VERSION 5.8 ;
BUSBITCHARS "" ;
DIVIDERCHAR "/" ;
UNITS DISTANCE MICRONS 2000 ;
# Merged SRAM library: SP (single-port) and DP (dual-port)
# Macros: SP128X33M2, SP128X33M4, SP512X40M2, SP512X40M4, DP128X64M4

MACRO SP128X33M2
  CLASS BLOCK ;
  ORIGIN 0.0 0.0 ;
  SIZE 15.0 BY 30.0 ;
  SYMMETRY X Y ;
  FOREIGN SP128X33M2 0.0 0.0 ;

  PIN CLK
    DIRECTION INPUT ;
    USE SIGNAL ;
    PORT
      LAYER M3 ;
      RECT 3.0 25.0 4.0 26.0 ;
    END
  END CLK

  PIN CS
    DIRECTION INPUT ;
    USE SIGNAL ;
    PORT
      LAYER M3 ;
      RECT 5.0 25.0 6.0 26.0 ;
    END
  END CS

  PIN WE
    DIRECTION INPUT ;
    USE SIGNAL ;
    PORT
      LAYER M3 ;
      RECT 7.0 25.0 8.0 26.0 ;
    END
  END WE

  PIN A[0]
    DIRECTION INPUT ;
    USE SIGNAL ;
    PORT
      LAYER M3 ;
      RECT 9.0 25.0 10.0 26.0 ;
    END
  END A[0]

  PIN A[1]
    DIRECTION INPUT ;
    USE SIGNAL ;
    PORT
      LAYER M3 ;
      RECT 10.0 25.0 11.0 26.0 ;
    END
  END A[1]

  PIN A[2]
    DIRECTION INPUT ;
    USE SIGNAL ;
    PORT
      LAYER M3 ;
      RECT 11.0 25.0 12.0 26.0 ;
    END
  END A[2]

  PIN A[3]
    DIRECTION INPUT ;
    USE SIGNAL ;
    PORT
      LAYER M3 ;
      RECT 12.0 25.0 13.0 26.0 ;
    END
  END A[3]

  PIN A[4]
    DIRECTION INPUT ;
    USE SIGNAL ;
    PORT
      LAYER M3 ;
      RECT 13.0 25.0 14.0 26.0 ;
    END
  END A[4]

  PIN A[5]
    DIRECTION INPUT ;
    USE SIGNAL ;
    PORT
      LAYER M3 ;
      RECT 14.0 25.0 15.0 26.0 ;
    END
  END A[5]

  PIN A[6]
    DIRECTION INPUT ;
    USE SIGNAL ;
    PORT
      LAYER M3 ;
      RECT 15.0 25.0 16.0 26.0 ;
    END
  END A[6]

  PIN D[0]
    DIRECTION INPUT ;
    USE SIGNAL ;
    PORT
      LAYER M3 ;
      RECT 9.0 27.0 10.0 28.0 ;
    END
  END D[0]

  PIN D[1]
    DIRECTION INPUT ;
    USE SIGNAL ;
    PORT
      LAYER M3 ;
      RECT 10.0 27.0 11.0 28.0 ;
    END
  END D[1]

  PIN D[2]
    DIRECTION INPUT ;
    USE SIGNAL ;
    PORT
      LAYER M3 ;
      RECT 11.0 27.0 12.0 28.0 ;
    END
  END D[2]

  PIN D[3]
    DIRECTION INPUT ;
    USE SIGNAL ;
    PORT
      LAYER M3 ;
      RECT 12.0 27.0 13.0 28.0 ;
    END
  END D[3]

  PIN D[4]
    DIRECTION INPUT ;
    USE SIGNAL ;
    PORT
      LAYER M3 ;
      RECT 13.0 27.0 14.0 28.0 ;
    END
  END D[4]

  PIN D[5]
    DIRECTION INPUT ;
    USE SIGNAL ;
    PORT
      LAYER M3 ;
      RECT 14.0 27.0 15.0 28.0 ;
    END
  END D[5]

  PIN D[6]
    DIRECTION INPUT ;
    USE SIGNAL ;
    PORT
      LAYER M3 ;
      RECT 9.0 28.0 10.0 29.0 ;
    END
  END D[6]

  PIN D[7]
    DIRECTION INPUT ;
    USE SIGNAL ;
    PORT
      LAYER M3 ;
      RECT 10.0 28.0 11.0 29.0 ;
    END
  END D[7]

  PIN D[8]
    DIRECTION INPUT ;
    USE SIGNAL ;
    PORT
      LAYER M3 ;
      RECT 11.0 28.0 12.0 29.0 ;
    END
  END D[8]

  PIN D[9]
    DIRECTION INPUT ;
    USE SIGNAL ;
    PORT
      LAYER M3 ;
      RECT 12.0 28.0 13.0 29.0 ;
    END
  END D[9]

  PIN D[10]
    DIRECTION INPUT ;
    USE SIGNAL ;
    PORT
      LAYER M3 ;
      RECT 13.0 28.0 14.0 29.0 ;
    END
  END D[10]

  PIN D[11]
    DIRECTION INPUT ;
    USE SIGNAL ;
    PORT
      LAYER M3 ;
      RECT 14.0 28.0 15.0 29.0 ;
    END
  END D[11]

  PIN D[12]
    DIRECTION INPUT ;
    USE SIGNAL ;
    PORT
      LAYER M3 ;
      RECT 9.0 29.0 10.0 30.0 ;
    END
  END D[12]

  PIN D[13]
    DIRECTION INPUT ;
    USE SIGNAL ;
    PORT
      LAYER M3 ;
      RECT 10.0 29.0 11.0 30.0 ;
    END
  END D[13]

  PIN D[14]
    DIRECTION INPUT ;
    USE SIGNAL ;
    PORT
      LAYER M3 ;
      RECT 11.0 29.0 12.0 30.0 ;
    END
  END D[14]

  PIN D[15]
    DIRECTION INPUT ;
    USE SIGNAL ;
    PORT
      LAYER M3 ;
      RECT 12.0 29.0 13.0 30.0 ;
    END
  END D[15]

  PIN D[16]
    DIRECTION INPUT ;
    USE SIGNAL ;
    PORT
      LAYER M3 ;
      RECT 13.0 29.0 14.0 30.0 ;
    END
  END D[16]

  PIN D[17]
    DIRECTION INPUT ;
    USE SIGNAL ;
    PORT
      LAYER M3 ;
      RECT 14.0 29.0 15.0 30.0 ;
    END
  END D[17]

  PIN D[18]
    DIRECTION INPUT ;
    USE SIGNAL ;
    PORT
      LAYER M3 ;
      RECT 9.0 30.0 10.0 31.0 ;
    END
  END D[18]

  PIN D[19]
    DIRECTION INPUT ;
    USE SIGNAL ;
    PORT
      LAYER M3 ;
      RECT 10.0 30.0 11.0 31.0 ;
    END
  END D[19]

  PIN D[20]
    DIRECTION INPUT ;
    USE SIGNAL ;
    PORT
      LAYER M3 ;
      RECT 11.0 30.0 12.0 31.0 ;
    END
  END D[20]

  PIN D[21]
    DIRECTION INPUT ;
    USE SIGNAL ;
    PORT
      LAYER M3 ;
      RECT 12.0 30.0 13.0 31.0 ;
    END
  END D[21]

  PIN D[22]
    DIRECTION INPUT ;
    USE SIGNAL ;
    PORT
      LAYER M3 ;
      RECT 13.0 30.0 14.0 31.0 ;
    END
  END D[22]

  PIN D[23]
    DIRECTION INPUT ;
    USE SIGNAL ;
    PORT
      LAYER M3 ;
      RECT 14.0 30.0 15.0 31.0 ;
    END
  END D[23]

  PIN D[24]
    DIRECTION INPUT ;
    USE SIGNAL ;
    PORT
      LAYER M3 ;
      RECT 9.0 31.0 10.0 32.0 ;
    END
  END D[24]

  PIN D[25]
    DIRECTION INPUT ;
    USE SIGNAL ;
    PORT
      LAYER M3 ;
      RECT 10.0 31.0 11.0 32.0 ;
    END
  END D[25]

  PIN D[26]
    DIRECTION INPUT ;
    USE SIGNAL ;
    PORT
      LAYER M3 ;
      RECT 11.0 31.0 12.0 32.0 ;
    END
  END D[26]

  PIN D[27]
    DIRECTION INPUT ;
    USE SIGNAL ;
    PORT
      LAYER M3 ;
      RECT 12.0 31.0 13.0 32.0 ;
    END
  END D[27]

  PIN D[28]
    DIRECTION INPUT ;
    USE SIGNAL ;
    PORT
      LAYER M3 ;
      RECT 13.0 31.0 14.0 32.0 ;
    END
  END D[28]

  PIN D[29]
    DIRECTION INPUT ;
    USE SIGNAL ;
    PORT
      LAYER M3 ;
      RECT 14.0 31.0 15.0 32.0 ;
    END
  END D[29]

  PIN D[30]
    DIRECTION INPUT ;
    USE SIGNAL ;
    PORT
      LAYER M3 ;
      RECT 9.0 32.0 10.0 33.0 ;
    END
  END D[30]

  PIN D[31]
    DIRECTION INPUT ;
    USE SIGNAL ;
    PORT
      LAYER M3 ;
      RECT 10.0 32.0 11.0 33.0 ;
    END
  END D[31]

  PIN D[32]
    DIRECTION INPUT ;
    USE SIGNAL ;
    PORT
      LAYER M3 ;
      RECT 11.0 32.0 12.0 33.0 ;
    END
  END D[32]

  PIN Q[0]
    DIRECTION OUTPUT ;
    USE SIGNAL ;
    PORT
      LAYER M3 ;
      RECT 9.0 2.0 10.0 3.0 ;
    END
  END Q[0]

  PIN Q[1]
    DIRECTION OUTPUT ;
    USE SIGNAL ;
    PORT
      LAYER M3 ;
      RECT 10.0 2.0 11.0 3.0 ;
    END
  END Q[1]

  PIN Q[2]
    DIRECTION OUTPUT ;
    USE SIGNAL ;
    PORT
      LAYER M3 ;
      RECT 11.0 2.0 12.0 3.0 ;
    END
  END Q[2]

  PIN Q[3]
    DIRECTION OUTPUT ;
    USE SIGNAL ;
    PORT
      LAYER M3 ;
      RECT 12.0 2.0 13.0 3.0 ;
    END
  END Q[3]

  PIN Q[4]
    DIRECTION OUTPUT ;
    USE SIGNAL ;
    PORT
      LAYER M3 ;
      RECT 13.0 2.0 14.0 3.0 ;
    END
  END Q[4]

  PIN Q[5]
    DIRECTION OUTPUT ;
    USE SIGNAL ;
    PORT
      LAYER M3 ;
      RECT 14.0 2.0 15.0 3.0 ;
    END
  END Q[5]

  PIN Q[6]
    DIRECTION OUTPUT ;
    USE SIGNAL ;
    PORT
      LAYER M3 ;
      RECT 9.0 3.0 10.0 4.0 ;
    END
  END Q[6]

  PIN Q[7]
    DIRECTION OUTPUT ;
    USE SIGNAL ;
    PORT
      LAYER M3 ;
      RECT 10.0 3.0 11.0 4.0 ;
    END
  END Q[7]

  PIN Q[8]
    DIRECTION OUTPUT ;
    USE SIGNAL ;
    PORT
      LAYER M3 ;
      RECT 11.0 3.0 12.0 4.0 ;
    END
  END Q[8]

  PIN Q[9]
    DIRECTION OUTPUT ;
    USE SIGNAL ;
    PORT
      LAYER M3 ;
      RECT 12.0 3.0 13.0 4.0 ;
    END
  END Q[9]

  PIN Q[10]
    DIRECTION OUTPUT ;
    USE SIGNAL ;
    PORT
      LAYER M3 ;
      RECT 13.0 3.0 14.0 4.0 ;
    END
  END Q[10]

  PIN Q[11]
    DIRECTION OUTPUT ;
    USE SIGNAL ;
    PORT
      LAYER M3 ;
      RECT 14.0 3.0 15.0 4.0 ;
    END
  END Q[11]

  PIN Q[12]
    DIRECTION OUTPUT ;
    USE SIGNAL ;
    PORT
      LAYER M3 ;
      RECT 9.0 4.0 10.0 5.0 ;
    END
  END Q[12]

  PIN Q[13]
    DIRECTION OUTPUT ;
    USE SIGNAL ;
    PORT
      LAYER M3 ;
      RECT 10.0 4.0 11.0 5.0 ;
    END
  END Q[13]

  PIN Q[14]
    DIRECTION OUTPUT ;
    USE SIGNAL ;
    PORT
      LAYER M3 ;
      RECT 11.0 4.0 12.0 5.0 ;
    END
  END Q[14]

  PIN Q[15]
    DIRECTION OUTPUT ;
    USE SIGNAL ;
    PORT
      LAYER M3 ;
      RECT 12.0 4.0 13.0 5.0 ;
    END
  END Q[15]

  PIN Q[16]
    DIRECTION OUTPUT ;
    USE SIGNAL ;
    PORT
      LAYER M3 ;
      RECT 13.0 4.0 14.0 5.0 ;
    END
  END Q[16]

  PIN Q[17]
    DIRECTION OUTPUT ;
    USE SIGNAL ;
    PORT
      LAYER M3 ;
      RECT 14.0 4.0 15.0 5.0 ;
    END
  END Q[17]

  PIN Q[18]
    DIRECTION OUTPUT ;
    USE SIGNAL ;
    PORT
      LAYER M3 ;
      RECT 9.0 5.0 10.0 6.0 ;
    END
  END Q[18]

  PIN Q[19]
    DIRECTION OUTPUT ;
    USE SIGNAL ;
    PORT
      LAYER M3 ;
      RECT 10.0 5.0 11.0 6.0 ;
    END
  END Q[19]

  PIN Q[20]
    DIRECTION OUTPUT ;
    USE SIGNAL ;
    PORT
      LAYER M3 ;
      RECT 11.0 5.0 12.0 6.0 ;
    END
  END Q[20]

  PIN Q[21]
    DIRECTION OUTPUT ;
    USE SIGNAL ;
    PORT
      LAYER M3 ;
      RECT 12.0 5.0 13.0 6.0 ;
    END
  END Q[21]

  PIN Q[22]
    DIRECTION OUTPUT ;
    USE SIGNAL ;
    PORT
      LAYER M3 ;
      RECT 13.0 5.0 14.0 6.0 ;
    END
  END Q[22]

  PIN Q[23]
    DIRECTION OUTPUT ;
    USE SIGNAL ;
    PORT
      LAYER M3 ;
      RECT 14.0 5.0 15.0 6.0 ;
    END
  END Q[23]

  PIN Q[24]
    DIRECTION OUTPUT ;
    USE SIGNAL ;
    PORT
      LAYER M3 ;
      RECT 9.0 6.0 10.0 7.0 ;
    END
  END Q[24]

  PIN Q[25]
    DIRECTION OUTPUT ;
    USE SIGNAL ;
    PORT
      LAYER M3 ;
      RECT 10.0 6.0 11.0 7.0 ;
    END
  END Q[25]

  PIN Q[26]
    DIRECTION OUTPUT ;
    USE SIGNAL ;
    PORT
      LAYER M3 ;
      RECT 11.0 6.0 12.0 7.0 ;
    END
  END Q[26]

  PIN Q[27]
    DIRECTION OUTPUT ;
    USE SIGNAL ;
    PORT
      LAYER M3 ;
      RECT 12.0 6.0 13.0 7.0 ;
    END
  END Q[27]

  PIN Q[28]
    DIRECTION OUTPUT ;
    USE SIGNAL ;
    PORT
      LAYER M3 ;
      RECT 13.0 6.0 14.0 7.0 ;
    END
  END Q[28]

  PIN Q[29]
    DIRECTION OUTPUT ;
    USE SIGNAL ;
    PORT
      LAYER M3 ;
      RECT 14.0 6.0 15.0 7.0 ;
    END
  END Q[29]

  PIN Q[30]
    DIRECTION OUTPUT ;
    USE SIGNAL ;
    PORT
      LAYER M3 ;
      RECT 9.0 7.0 10.0 8.0 ;
    END
  END Q[30]

  PIN Q[31]
    DIRECTION OUTPUT ;
    USE SIGNAL ;
    PORT
      LAYER M3 ;
      RECT 10.0 7.0 11.0 8.0 ;
    END
  END Q[31]

  PIN Q[32]
    DIRECTION OUTPUT ;
    USE SIGNAL ;
    PORT
      LAYER M3 ;
      RECT 11.0 7.0 12.0 8.0 ;
    END
  END Q[32]

END SP128X33M2

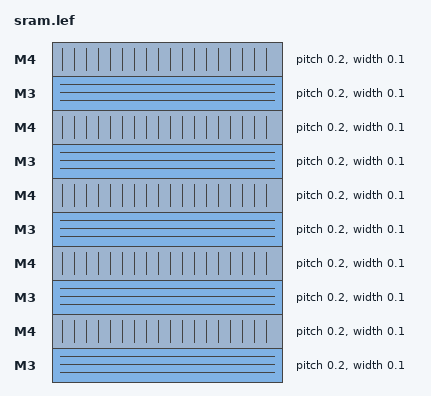
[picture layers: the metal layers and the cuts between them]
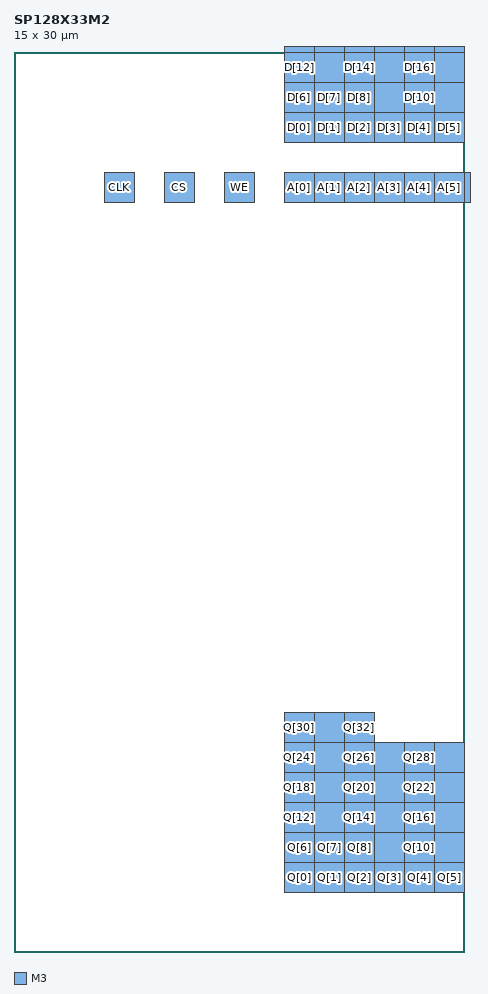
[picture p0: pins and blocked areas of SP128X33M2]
LAYER M3
  TYPE ROUTING ;
  DIRECTION HORIZONTAL ;
  PITCH 0.2 ;
  WIDTH 0.1 ;
END M3

LAYER M4
  TYPE ROUTING ;
  DIRECTION VERTICAL ;
  PITCH 0.2 ;
  WIDTH 0.1 ;
END M4

SITE BLOCK
  CLASS BLOCK ;
  SIZE 1.0 BY 1.0 ;
  SYMMETRY X Y ;
END BLOCK


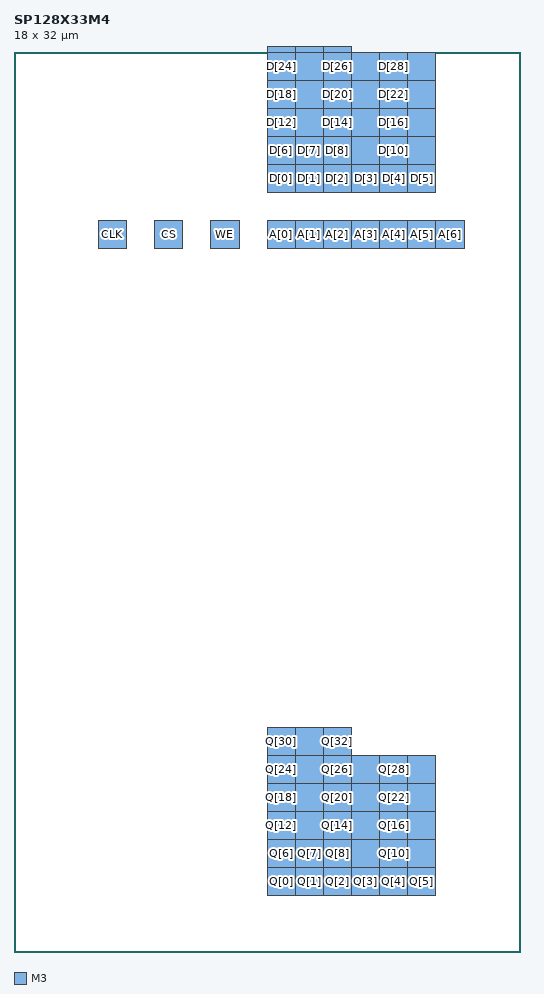
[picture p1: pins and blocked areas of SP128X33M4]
MACRO SP128X33M4
  CLASS BLOCK ;
  ORIGIN 0.0 0.0 ;
  SIZE 18.0 BY 32.0 ;
  SYMMETRY X Y ;
  FOREIGN SP128X33M4 0.0 0.0 ;

  PIN CLK
    DIRECTION INPUT ;
    USE SIGNAL ;
    PORT
      LAYER M3 ;
      RECT 3.0 25.0 4.0 26.0 ;
    END
  END CLK

  PIN CS
    DIRECTION INPUT ;
    USE SIGNAL ;
    PORT
      LAYER M3 ;
      RECT 5.0 25.0 6.0 26.0 ;
    END
  END CS

  PIN WE
    DIRECTION INPUT ;
    USE SIGNAL ;
    PORT
      LAYER M3 ;
      RECT 7.0 25.0 8.0 26.0 ;
    END
  END WE

  PIN A[0]
    DIRECTION INPUT ;
    USE SIGNAL ;
    PORT
      LAYER M3 ;
      RECT 9.0 25.0 10.0 26.0 ;
    END
  END A[0]

  PIN A[1]
    DIRECTION INPUT ;
    USE SIGNAL ;
    PORT
      LAYER M3 ;
      RECT 10.0 25.0 11.0 26.0 ;
    END
  END A[1]

  PIN A[2]
    DIRECTION INPUT ;
    USE SIGNAL ;
    PORT
      LAYER M3 ;
      RECT 11.0 25.0 12.0 26.0 ;
    END
  END A[2]

  PIN A[3]
    DIRECTION INPUT ;
    USE SIGNAL ;
    PORT
      LAYER M3 ;
      RECT 12.0 25.0 13.0 26.0 ;
    END
  END A[3]

  PIN A[4]
    DIRECTION INPUT ;
    USE SIGNAL ;
    PORT
      LAYER M3 ;
      RECT 13.0 25.0 14.0 26.0 ;
    END
  END A[4]

  PIN A[5]
    DIRECTION INPUT ;
    USE SIGNAL ;
    PORT
      LAYER M3 ;
      RECT 14.0 25.0 15.0 26.0 ;
    END
  END A[5]

  PIN A[6]
    DIRECTION INPUT ;
    USE SIGNAL ;
    PORT
      LAYER M3 ;
      RECT 15.0 25.0 16.0 26.0 ;
    END
  END A[6]

  PIN D[0]
    DIRECTION INPUT ;
    USE SIGNAL ;
    PORT
      LAYER M3 ;
      RECT 9.0 27.0 10.0 28.0 ;
    END
  END D[0]

  PIN D[1]
    DIRECTION INPUT ;
    USE SIGNAL ;
    PORT
      LAYER M3 ;
      RECT 10.0 27.0 11.0 28.0 ;
    END
  END D[1]

  PIN D[2]
    DIRECTION INPUT ;
    USE SIGNAL ;
    PORT
      LAYER M3 ;
      RECT 11.0 27.0 12.0 28.0 ;
    END
  END D[2]

  PIN D[3]
    DIRECTION INPUT ;
    USE SIGNAL ;
    PORT
      LAYER M3 ;
      RECT 12.0 27.0 13.0 28.0 ;
    END
  END D[3]

  PIN D[4]
    DIRECTION INPUT ;
    USE SIGNAL ;
    PORT
      LAYER M3 ;
      RECT 13.0 27.0 14.0 28.0 ;
    END
  END D[4]

  PIN D[5]
    DIRECTION INPUT ;
    USE SIGNAL ;
    PORT
      LAYER M3 ;
      RECT 14.0 27.0 15.0 28.0 ;
    END
  END D[5]

  PIN D[6]
    DIRECTION INPUT ;
    USE SIGNAL ;
    PORT
      LAYER M3 ;
      RECT 9.0 28.0 10.0 29.0 ;
    END
  END D[6]

  PIN D[7]
    DIRECTION INPUT ;
    USE SIGNAL ;
    PORT
      LAYER M3 ;
      RECT 10.0 28.0 11.0 29.0 ;
    END
  END D[7]

  PIN D[8]
    DIRECTION INPUT ;
    USE SIGNAL ;
    PORT
      LAYER M3 ;
      RECT 11.0 28.0 12.0 29.0 ;
    END
  END D[8]

  PIN D[9]
    DIRECTION INPUT ;
    USE SIGNAL ;
    PORT
      LAYER M3 ;
      RECT 12.0 28.0 13.0 29.0 ;
    END
  END D[9]

  PIN D[10]
    DIRECTION INPUT ;
    USE SIGNAL ;
    PORT
      LAYER M3 ;
      RECT 13.0 28.0 14.0 29.0 ;
    END
  END D[10]

  PIN D[11]
    DIRECTION INPUT ;
    USE SIGNAL ;
    PORT
      LAYER M3 ;
      RECT 14.0 28.0 15.0 29.0 ;
    END
  END D[11]

  PIN D[12]
    DIRECTION INPUT ;
    USE SIGNAL ;
    PORT
      LAYER M3 ;
      RECT 9.0 29.0 10.0 30.0 ;
    END
  END D[12]

  PIN D[13]
    DIRECTION INPUT ;
    USE SIGNAL ;
    PORT
      LAYER M3 ;
      RECT 10.0 29.0 11.0 30.0 ;
    END
  END D[13]

  PIN D[14]
    DIRECTION INPUT ;
    USE SIGNAL ;
    PORT
      LAYER M3 ;
      RECT 11.0 29.0 12.0 30.0 ;
    END
  END D[14]

  PIN D[15]
    DIRECTION INPUT ;
    USE SIGNAL ;
    PORT
      LAYER M3 ;
      RECT 12.0 29.0 13.0 30.0 ;
    END
  END D[15]

  PIN D[16]
    DIRECTION INPUT ;
    USE SIGNAL ;
    PORT
      LAYER M3 ;
      RECT 13.0 29.0 14.0 30.0 ;
    END
  END D[16]

  PIN D[17]
    DIRECTION INPUT ;
    USE SIGNAL ;
    PORT
      LAYER M3 ;
      RECT 14.0 29.0 15.0 30.0 ;
    END
  END D[17]

  PIN D[18]
    DIRECTION INPUT ;
    USE SIGNAL ;
    PORT
      LAYER M3 ;
      RECT 9.0 30.0 10.0 31.0 ;
    END
  END D[18]

  PIN D[19]
    DIRECTION INPUT ;
    USE SIGNAL ;
    PORT
      LAYER M3 ;
      RECT 10.0 30.0 11.0 31.0 ;
    END
  END D[19]

  PIN D[20]
    DIRECTION INPUT ;
    USE SIGNAL ;
    PORT
      LAYER M3 ;
      RECT 11.0 30.0 12.0 31.0 ;
    END
  END D[20]

  PIN D[21]
    DIRECTION INPUT ;
    USE SIGNAL ;
    PORT
      LAYER M3 ;
      RECT 12.0 30.0 13.0 31.0 ;
    END
  END D[21]

  PIN D[22]
    DIRECTION INPUT ;
    USE SIGNAL ;
    PORT
      LAYER M3 ;
      RECT 13.0 30.0 14.0 31.0 ;
    END
  END D[22]

  PIN D[23]
    DIRECTION INPUT ;
    USE SIGNAL ;
    PORT
      LAYER M3 ;
      RECT 14.0 30.0 15.0 31.0 ;
    END
  END D[23]

  PIN D[24]
    DIRECTION INPUT ;
    USE SIGNAL ;
    PORT
      LAYER M3 ;
      RECT 9.0 31.0 10.0 32.0 ;
    END
  END D[24]

  PIN D[25]
    DIRECTION INPUT ;
    USE SIGNAL ;
    PORT
      LAYER M3 ;
      RECT 10.0 31.0 11.0 32.0 ;
    END
  END D[25]

  PIN D[26]
    DIRECTION INPUT ;
    USE SIGNAL ;
    PORT
      LAYER M3 ;
      RECT 11.0 31.0 12.0 32.0 ;
    END
  END D[26]

  PIN D[27]
    DIRECTION INPUT ;
    USE SIGNAL ;
    PORT
      LAYER M3 ;
      RECT 12.0 31.0 13.0 32.0 ;
    END
  END D[27]

  PIN D[28]
    DIRECTION INPUT ;
    USE SIGNAL ;
    PORT
      LAYER M3 ;
      RECT 13.0 31.0 14.0 32.0 ;
    END
  END D[28]

  PIN D[29]
    DIRECTION INPUT ;
    USE SIGNAL ;
    PORT
      LAYER M3 ;
      RECT 14.0 31.0 15.0 32.0 ;
    END
  END D[29]

  PIN D[30]
    DIRECTION INPUT ;
    USE SIGNAL ;
    PORT
      LAYER M3 ;
      RECT 9.0 32.0 10.0 33.0 ;
    END
  END D[30]

  PIN D[31]
    DIRECTION INPUT ;
    USE SIGNAL ;
    PORT
      LAYER M3 ;
      RECT 10.0 32.0 11.0 33.0 ;
    END
  END D[31]

  PIN D[32]
    DIRECTION INPUT ;
    USE SIGNAL ;
    PORT
      LAYER M3 ;
      RECT 11.0 32.0 12.0 33.0 ;
    END
  END D[32]

  PIN Q[0]
    DIRECTION OUTPUT ;
    USE SIGNAL ;
    PORT
      LAYER M3 ;
      RECT 9.0 2.0 10.0 3.0 ;
    END
  END Q[0]

  PIN Q[1]
    DIRECTION OUTPUT ;
    USE SIGNAL ;
    PORT
      LAYER M3 ;
      RECT 10.0 2.0 11.0 3.0 ;
    END
  END Q[1]

  PIN Q[2]
    DIRECTION OUTPUT ;
    USE SIGNAL ;
    PORT
      LAYER M3 ;
      RECT 11.0 2.0 12.0 3.0 ;
    END
  END Q[2]

  PIN Q[3]
    DIRECTION OUTPUT ;
    USE SIGNAL ;
    PORT
      LAYER M3 ;
      RECT 12.0 2.0 13.0 3.0 ;
    END
  END Q[3]

  PIN Q[4]
    DIRECTION OUTPUT ;
    USE SIGNAL ;
    PORT
      LAYER M3 ;
      RECT 13.0 2.0 14.0 3.0 ;
    END
  END Q[4]

  PIN Q[5]
    DIRECTION OUTPUT ;
    USE SIGNAL ;
    PORT
      LAYER M3 ;
      RECT 14.0 2.0 15.0 3.0 ;
    END
  END Q[5]

  PIN Q[6]
    DIRECTION OUTPUT ;
    USE SIGNAL ;
    PORT
      LAYER M3 ;
      RECT 9.0 3.0 10.0 4.0 ;
    END
  END Q[6]

  PIN Q[7]
    DIRECTION OUTPUT ;
    USE SIGNAL ;
    PORT
      LAYER M3 ;
      RECT 10.0 3.0 11.0 4.0 ;
    END
  END Q[7]

  PIN Q[8]
    DIRECTION OUTPUT ;
    USE SIGNAL ;
    PORT
      LAYER M3 ;
      RECT 11.0 3.0 12.0 4.0 ;
    END
  END Q[8]

  PIN Q[9]
    DIRECTION OUTPUT ;
    USE SIGNAL ;
    PORT
      LAYER M3 ;
      RECT 12.0 3.0 13.0 4.0 ;
    END
  END Q[9]

  PIN Q[10]
    DIRECTION OUTPUT ;
    USE SIGNAL ;
    PORT
      LAYER M3 ;
      RECT 13.0 3.0 14.0 4.0 ;
    END
  END Q[10]

  PIN Q[11]
    DIRECTION OUTPUT ;
    USE SIGNAL ;
    PORT
      LAYER M3 ;
      RECT 14.0 3.0 15.0 4.0 ;
    END
  END Q[11]

  PIN Q[12]
    DIRECTION OUTPUT ;
    USE SIGNAL ;
    PORT
      LAYER M3 ;
      RECT 9.0 4.0 10.0 5.0 ;
    END
  END Q[12]

  PIN Q[13]
    DIRECTION OUTPUT ;
    USE SIGNAL ;
    PORT
      LAYER M3 ;
      RECT 10.0 4.0 11.0 5.0 ;
    END
  END Q[13]

  PIN Q[14]
    DIRECTION OUTPUT ;
    USE SIGNAL ;
    PORT
      LAYER M3 ;
      RECT 11.0 4.0 12.0 5.0 ;
    END
  END Q[14]

  PIN Q[15]
    DIRECTION OUTPUT ;
    USE SIGNAL ;
    PORT
      LAYER M3 ;
      RECT 12.0 4.0 13.0 5.0 ;
    END
  END Q[15]

  PIN Q[16]
    DIRECTION OUTPUT ;
    USE SIGNAL ;
    PORT
      LAYER M3 ;
      RECT 13.0 4.0 14.0 5.0 ;
    END
  END Q[16]

  PIN Q[17]
    DIRECTION OUTPUT ;
    USE SIGNAL ;
    PORT
      LAYER M3 ;
      RECT 14.0 4.0 15.0 5.0 ;
    END
  END Q[17]

  PIN Q[18]
    DIRECTION OUTPUT ;
    USE SIGNAL ;
    PORT
      LAYER M3 ;
      RECT 9.0 5.0 10.0 6.0 ;
    END
  END Q[18]

  PIN Q[19]
    DIRECTION OUTPUT ;
    USE SIGNAL ;
    PORT
      LAYER M3 ;
      RECT 10.0 5.0 11.0 6.0 ;
    END
  END Q[19]

  PIN Q[20]
    DIRECTION OUTPUT ;
    USE SIGNAL ;
    PORT
      LAYER M3 ;
      RECT 11.0 5.0 12.0 6.0 ;
    END
  END Q[20]

  PIN Q[21]
    DIRECTION OUTPUT ;
    USE SIGNAL ;
    PORT
      LAYER M3 ;
      RECT 12.0 5.0 13.0 6.0 ;
    END
  END Q[21]

  PIN Q[22]
    DIRECTION OUTPUT ;
    USE SIGNAL ;
    PORT
      LAYER M3 ;
      RECT 13.0 5.0 14.0 6.0 ;
    END
  END Q[22]

  PIN Q[23]
    DIRECTION OUTPUT ;
    USE SIGNAL ;
    PORT
      LAYER M3 ;
      RECT 14.0 5.0 15.0 6.0 ;
    END
  END Q[23]

  PIN Q[24]
    DIRECTION OUTPUT ;
    USE SIGNAL ;
    PORT
      LAYER M3 ;
      RECT 9.0 6.0 10.0 7.0 ;
    END
  END Q[24]

  PIN Q[25]
    DIRECTION OUTPUT ;
    USE SIGNAL ;
    PORT
      LAYER M3 ;
      RECT 10.0 6.0 11.0 7.0 ;
    END
  END Q[25]

  PIN Q[26]
    DIRECTION OUTPUT ;
    USE SIGNAL ;
    PORT
      LAYER M3 ;
      RECT 11.0 6.0 12.0 7.0 ;
    END
  END Q[26]

  PIN Q[27]
    DIRECTION OUTPUT ;
    USE SIGNAL ;
    PORT
      LAYER M3 ;
      RECT 12.0 6.0 13.0 7.0 ;
    END
  END Q[27]

  PIN Q[28]
    DIRECTION OUTPUT ;
    USE SIGNAL ;
    PORT
      LAYER M3 ;
      RECT 13.0 6.0 14.0 7.0 ;
    END
  END Q[28]

  PIN Q[29]
    DIRECTION OUTPUT ;
    USE SIGNAL ;
    PORT
      LAYER M3 ;
      RECT 14.0 6.0 15.0 7.0 ;
    END
  END Q[29]

  PIN Q[30]
    DIRECTION OUTPUT ;
    USE SIGNAL ;
    PORT
      LAYER M3 ;
      RECT 9.0 7.0 10.0 8.0 ;
    END
  END Q[30]

  PIN Q[31]
    DIRECTION OUTPUT ;
    USE SIGNAL ;
    PORT
      LAYER M3 ;
      RECT 10.0 7.0 11.0 8.0 ;
    END
  END Q[31]

  PIN Q[32]
    DIRECTION OUTPUT ;
    USE SIGNAL ;
    PORT
      LAYER M3 ;
      RECT 11.0 7.0 12.0 8.0 ;
    END
  END Q[32]

END SP128X33M4

LAYER M3
  TYPE ROUTING ;
  DIRECTION HORIZONTAL ;
  PITCH 0.2 ;
  WIDTH 0.1 ;
END M3

LAYER M4
  TYPE ROUTING ;
  DIRECTION VERTICAL ;
  PITCH 0.2 ;
  WIDTH 0.1 ;
END M4

SITE BLOCK
  CLASS BLOCK ;
  SIZE 1.0 BY 1.0 ;
  SYMMETRY X Y ;
END BLOCK


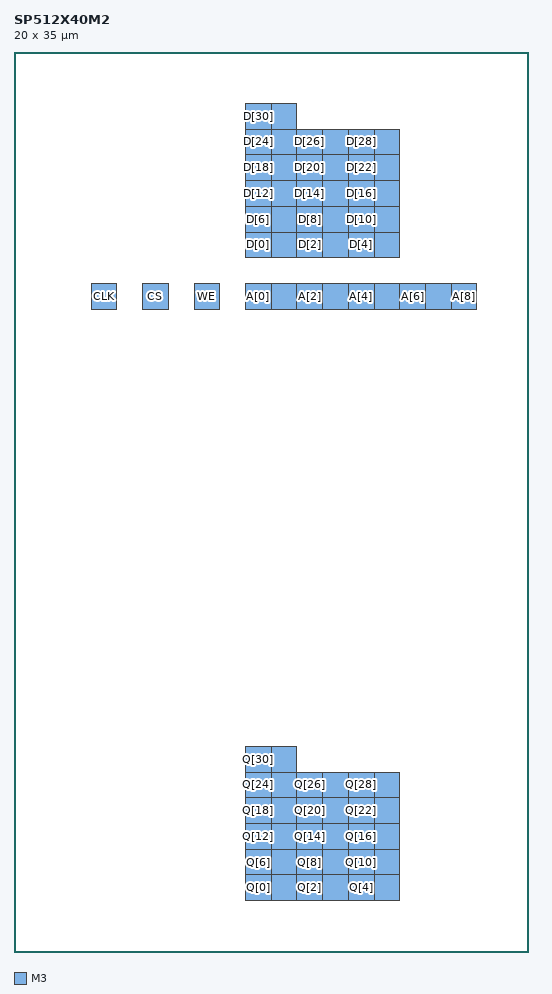
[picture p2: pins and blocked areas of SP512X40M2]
MACRO SP512X40M2
  CLASS BLOCK ;
  ORIGIN 0.0 0.0 ;
  SIZE 20.0 BY 35.0 ;
  SYMMETRY X Y ;
  FOREIGN SP512X40M2 0.0 0.0 ;

  PIN CLK
    DIRECTION INPUT ;
    USE SIGNAL ;
    PORT
      LAYER M3 ;
      RECT 3.0 25.0 4.0 26.0 ;
    END
  END CLK

  PIN CS
    DIRECTION INPUT ;
    USE SIGNAL ;
    PORT
      LAYER M3 ;
      RECT 5.0 25.0 6.0 26.0 ;
    END
  END CS

  PIN WE
    DIRECTION INPUT ;
    USE SIGNAL ;
    PORT
      LAYER M3 ;
      RECT 7.0 25.0 8.0 26.0 ;
    END
  END WE

  PIN A[0]
    DIRECTION INPUT ;
    USE SIGNAL ;
    PORT
      LAYER M3 ;
      RECT 9.0 25.0 10.0 26.0 ;
    END
  END A[0]

  PIN A[1]
    DIRECTION INPUT ;
    USE SIGNAL ;
    PORT
      LAYER M3 ;
      RECT 10.0 25.0 11.0 26.0 ;
    END
  END A[1]

  PIN A[2]
    DIRECTION INPUT ;
    USE SIGNAL ;
    PORT
      LAYER M3 ;
      RECT 11.0 25.0 12.0 26.0 ;
    END
  END A[2]

  PIN A[3]
    DIRECTION INPUT ;
    USE SIGNAL ;
    PORT
      LAYER M3 ;
      RECT 12.0 25.0 13.0 26.0 ;
    END
  END A[3]

  PIN A[4]
    DIRECTION INPUT ;
    USE SIGNAL ;
    PORT
      LAYER M3 ;
      RECT 13.0 25.0 14.0 26.0 ;
    END
  END A[4]

  PIN A[5]
    DIRECTION INPUT ;
    USE SIGNAL ;
    PORT
      LAYER M3 ;
      RECT 14.0 25.0 15.0 26.0 ;
    END
  END A[5]

  PIN A[6]
    DIRECTION INPUT ;
    USE SIGNAL ;
    PORT
      LAYER M3 ;
      RECT 15.0 25.0 16.0 26.0 ;
    END
  END A[6]

  PIN A[7]
    DIRECTION INPUT ;
    USE SIGNAL ;
    PORT
      LAYER M3 ;
      RECT 16.0 25.0 17.0 26.0 ;
    END
  END A[7]

  PIN A[8]
    DIRECTION INPUT ;
    USE SIGNAL ;
    PORT
      LAYER M3 ;
      RECT 17.0 25.0 18.0 26.0 ;
    END
  END A[8]

  PIN D[0]
    DIRECTION INPUT ;
    USE SIGNAL ;
    PORT
      LAYER M3 ;
      RECT 9.0 27.0 10.0 28.0 ;
    END
  END D[0]

  PIN D[1]
    DIRECTION INPUT ;
    USE SIGNAL ;
    PORT
      LAYER M3 ;
      RECT 10.0 27.0 11.0 28.0 ;
    END
  END D[1]

  PIN D[2]
    DIRECTION INPUT ;
    USE SIGNAL ;
    PORT
      LAYER M3 ;
      RECT 11.0 27.0 12.0 28.0 ;
    END
  END D[2]

  PIN D[3]
    DIRECTION INPUT ;
    USE SIGNAL ;
    PORT
      LAYER M3 ;
      RECT 12.0 27.0 13.0 28.0 ;
    END
  END D[3]

  PIN D[4]
    DIRECTION INPUT ;
    USE SIGNAL ;
    PORT
      LAYER M3 ;
      RECT 13.0 27.0 14.0 28.0 ;
    END
  END D[4]

  PIN D[5]
    DIRECTION INPUT ;
    USE SIGNAL ;
    PORT
      LAYER M3 ;
      RECT 14.0 27.0 15.0 28.0 ;
    END
  END D[5]

  PIN D[6]
    DIRECTION INPUT ;
    USE SIGNAL ;
    PORT
      LAYER M3 ;
      RECT 9.0 28.0 10.0 29.0 ;
    END
  END D[6]

  PIN D[7]
    DIRECTION INPUT ;
    USE SIGNAL ;
    PORT
      LAYER M3 ;
      RECT 10.0 28.0 11.0 29.0 ;
    END
  END D[7]

  PIN D[8]
    DIRECTION INPUT ;
    USE SIGNAL ;
    PORT
      LAYER M3 ;
      RECT 11.0 28.0 12.0 29.0 ;
    END
  END D[8]

  PIN D[9]
    DIRECTION INPUT ;
    USE SIGNAL ;
    PORT
      LAYER M3 ;
      RECT 12.0 28.0 13.0 29.0 ;
    END
  END D[9]

  PIN D[10]
    DIRECTION INPUT ;
    USE SIGNAL ;
    PORT
      LAYER M3 ;
      RECT 13.0 28.0 14.0 29.0 ;
    END
  END D[10]

  PIN D[11]
    DIRECTION INPUT ;
    USE SIGNAL ;
    PORT
      LAYER M3 ;
      RECT 14.0 28.0 15.0 29.0 ;
    END
  END D[11]

  PIN D[12]
    DIRECTION INPUT ;
    USE SIGNAL ;
    PORT
      LAYER M3 ;
      RECT 9.0 29.0 10.0 30.0 ;
    END
  END D[12]

  PIN D[13]
    DIRECTION INPUT ;
    USE SIGNAL ;
    PORT
      LAYER M3 ;
      RECT 10.0 29.0 11.0 30.0 ;
    END
  END D[13]

  PIN D[14]
    DIRECTION INPUT ;
    USE SIGNAL ;
    PORT
      LAYER M3 ;
      RECT 11.0 29.0 12.0 30.0 ;
    END
  END D[14]

  PIN D[15]
    DIRECTION INPUT ;
    USE SIGNAL ;
    PORT
      LAYER M3 ;
      RECT 12.0 29.0 13.0 30.0 ;
    END
  END D[15]

  PIN D[16]
    DIRECTION INPUT ;
    USE SIGNAL ;
    PORT
      LAYER M3 ;
      RECT 13.0 29.0 14.0 30.0 ;
    END
  END D[16]

  PIN D[17]
    DIRECTION INPUT ;
    USE SIGNAL ;
    PORT
      LAYER M3 ;
      RECT 14.0 29.0 15.0 30.0 ;
    END
  END D[17]

  PIN D[18]
    DIRECTION INPUT ;
    USE SIGNAL ;
    PORT
      LAYER M3 ;
      RECT 9.0 30.0 10.0 31.0 ;
    END
  END D[18]

  PIN D[19]
    DIRECTION INPUT ;
    USE SIGNAL ;
    PORT
      LAYER M3 ;
      RECT 10.0 30.0 11.0 31.0 ;
    END
  END D[19]

  PIN D[20]
    DIRECTION INPUT ;
    USE SIGNAL ;
    PORT
      LAYER M3 ;
      RECT 11.0 30.0 12.0 31.0 ;
    END
  END D[20]

  PIN D[21]
    DIRECTION INPUT ;
    USE SIGNAL ;
    PORT
      LAYER M3 ;
      RECT 12.0 30.0 13.0 31.0 ;
    END
  END D[21]

  PIN D[22]
    DIRECTION INPUT ;
    USE SIGNAL ;
    PORT
      LAYER M3 ;
      RECT 13.0 30.0 14.0 31.0 ;
    END
  END D[22]

  PIN D[23]
    DIRECTION INPUT ;
    USE SIGNAL ;
    PORT
      LAYER M3 ;
      RECT 14.0 30.0 15.0 31.0 ;
    END
  END D[23]

  PIN D[24]
    DIRECTION INPUT ;
    USE SIGNAL ;
    PORT
      LAYER M3 ;
      RECT 9.0 31.0 10.0 32.0 ;
    END
  END D[24]

  PIN D[25]
    DIRECTION INPUT ;
    USE SIGNAL ;
    PORT
      LAYER M3 ;
      RECT 10.0 31.0 11.0 32.0 ;
    END
  END D[25]

  PIN D[26]
    DIRECTION INPUT ;
    USE SIGNAL ;
    PORT
      LAYER M3 ;
      RECT 11.0 31.0 12.0 32.0 ;
    END
  END D[26]

  PIN D[27]
    DIRECTION INPUT ;
    USE SIGNAL ;
    PORT
      LAYER M3 ;
      RECT 12.0 31.0 13.0 32.0 ;
    END
  END D[27]

  PIN D[28]
    DIRECTION INPUT ;
    USE SIGNAL ;
    PORT
      LAYER M3 ;
      RECT 13.0 31.0 14.0 32.0 ;
    END
  END D[28]

  PIN D[29]
    DIRECTION INPUT ;
    USE SIGNAL ;
    PORT
      LAYER M3 ;
      RECT 14.0 31.0 15.0 32.0 ;
    END
  END D[29]

  PIN D[30]
    DIRECTION INPUT ;
    USE SIGNAL ;
    PORT
      LAYER M3 ;
      RECT 9.0 32.0 10.0 33.0 ;
    END
  END D[30]

  PIN D[31]
    DIRECTION INPUT ;
    USE SIGNAL ;
    PORT
      LAYER M3 ;
      RECT 10.0 32.0 11.0 33.0 ;
    END
  END D[31]

  PIN Q[0]
    DIRECTION OUTPUT ;
    USE SIGNAL ;
    PORT
      LAYER M3 ;
      RECT 9.0 2.0 10.0 3.0 ;
    END
  END Q[0]

  PIN Q[1]
    DIRECTION OUTPUT ;
    USE SIGNAL ;
    PORT
      LAYER M3 ;
      RECT 10.0 2.0 11.0 3.0 ;
    END
  END Q[1]

  PIN Q[2]
    DIRECTION OUTPUT ;
    USE SIGNAL ;
    PORT
      LAYER M3 ;
      RECT 11.0 2.0 12.0 3.0 ;
    END
  END Q[2]

  PIN Q[3]
    DIRECTION OUTPUT ;
    USE SIGNAL ;
    PORT
      LAYER M3 ;
      RECT 12.0 2.0 13.0 3.0 ;
    END
  END Q[3]

  PIN Q[4]
    DIRECTION OUTPUT ;
    USE SIGNAL ;
    PORT
      LAYER M3 ;
      RECT 13.0 2.0 14.0 3.0 ;
    END
  END Q[4]

  PIN Q[5]
    DIRECTION OUTPUT ;
    USE SIGNAL ;
    PORT
      LAYER M3 ;
      RECT 14.0 2.0 15.0 3.0 ;
    END
  END Q[5]

  PIN Q[6]
    DIRECTION OUTPUT ;
    USE SIGNAL ;
    PORT
      LAYER M3 ;
      RECT 9.0 3.0 10.0 4.0 ;
    END
  END Q[6]

  PIN Q[7]
    DIRECTION OUTPUT ;
    USE SIGNAL ;
    PORT
      LAYER M3 ;
      RECT 10.0 3.0 11.0 4.0 ;
    END
  END Q[7]

  PIN Q[8]
    DIRECTION OUTPUT ;
    USE SIGNAL ;
    PORT
      LAYER M3 ;
      RECT 11.0 3.0 12.0 4.0 ;
    END
  END Q[8]

  PIN Q[9]
    DIRECTION OUTPUT ;
    USE SIGNAL ;
    PORT
      LAYER M3 ;
      RECT 12.0 3.0 13.0 4.0 ;
    END
  END Q[9]

  PIN Q[10]
    DIRECTION OUTPUT ;
    USE SIGNAL ;
    PORT
      LAYER M3 ;
      RECT 13.0 3.0 14.0 4.0 ;
    END
  END Q[10]

  PIN Q[11]
    DIRECTION OUTPUT ;
    USE SIGNAL ;
    PORT
      LAYER M3 ;
      RECT 14.0 3.0 15.0 4.0 ;
    END
  END Q[11]

  PIN Q[12]
    DIRECTION OUTPUT ;
    USE SIGNAL ;
    PORT
      LAYER M3 ;
      RECT 9.0 4.0 10.0 5.0 ;
    END
  END Q[12]

  PIN Q[13]
    DIRECTION OUTPUT ;
    USE SIGNAL ;
    PORT
      LAYER M3 ;
      RECT 10.0 4.0 11.0 5.0 ;
    END
  END Q[13]

  PIN Q[14]
    DIRECTION OUTPUT ;
    USE SIGNAL ;
    PORT
      LAYER M3 ;
      RECT 11.0 4.0 12.0 5.0 ;
    END
  END Q[14]

  PIN Q[15]
    DIRECTION OUTPUT ;
    USE SIGNAL ;
    PORT
      LAYER M3 ;
      RECT 12.0 4.0 13.0 5.0 ;
    END
  END Q[15]

  PIN Q[16]
    DIRECTION OUTPUT ;
    USE SIGNAL ;
    PORT
      LAYER M3 ;
      RECT 13.0 4.0 14.0 5.0 ;
    END
  END Q[16]

  PIN Q[17]
    DIRECTION OUTPUT ;
    USE SIGNAL ;
    PORT
      LAYER M3 ;
      RECT 14.0 4.0 15.0 5.0 ;
    END
  END Q[17]

  PIN Q[18]
    DIRECTION OUTPUT ;
    USE SIGNAL ;
    PORT
      LAYER M3 ;
      RECT 9.0 5.0 10.0 6.0 ;
    END
  END Q[18]

  PIN Q[19]
    DIRECTION OUTPUT ;
    USE SIGNAL ;
    PORT
      LAYER M3 ;
      RECT 10.0 5.0 11.0 6.0 ;
    END
  END Q[19]

  PIN Q[20]
    DIRECTION OUTPUT ;
    USE SIGNAL ;
    PORT
      LAYER M3 ;
      RECT 11.0 5.0 12.0 6.0 ;
    END
  END Q[20]

  PIN Q[21]
    DIRECTION OUTPUT ;
    USE SIGNAL ;
    PORT
      LAYER M3 ;
      RECT 12.0 5.0 13.0 6.0 ;
    END
  END Q[21]

  PIN Q[22]
    DIRECTION OUTPUT ;
    USE SIGNAL ;
    PORT
      LAYER M3 ;
      RECT 13.0 5.0 14.0 6.0 ;
    END
  END Q[22]

  PIN Q[23]
    DIRECTION OUTPUT ;
    USE SIGNAL ;
    PORT
      LAYER M3 ;
      RECT 14.0 5.0 15.0 6.0 ;
    END
  END Q[23]

  PIN Q[24]
    DIRECTION OUTPUT ;
    USE SIGNAL ;
    PORT
      LAYER M3 ;
      RECT 9.0 6.0 10.0 7.0 ;
    END
  END Q[24]

  PIN Q[25]
    DIRECTION OUTPUT ;
    USE SIGNAL ;
    PORT
      LAYER M3 ;
      RECT 10.0 6.0 11.0 7.0 ;
    END
  END Q[25]

  PIN Q[26]
    DIRECTION OUTPUT ;
    USE SIGNAL ;
    PORT
      LAYER M3 ;
      RECT 11.0 6.0 12.0 7.0 ;
    END
  END Q[26]

  PIN Q[27]
    DIRECTION OUTPUT ;
    USE SIGNAL ;
    PORT
      LAYER M3 ;
      RECT 12.0 6.0 13.0 7.0 ;
    END
  END Q[27]

  PIN Q[28]
    DIRECTION OUTPUT ;
    USE SIGNAL ;
    PORT
      LAYER M3 ;
      RECT 13.0 6.0 14.0 7.0 ;
    END
  END Q[28]

  PIN Q[29]
    DIRECTION OUTPUT ;
    USE SIGNAL ;
    PORT
      LAYER M3 ;
      RECT 14.0 6.0 15.0 7.0 ;
    END
  END Q[29]

  PIN Q[30]
    DIRECTION OUTPUT ;
    USE SIGNAL ;
    PORT
      LAYER M3 ;
      RECT 9.0 7.0 10.0 8.0 ;
    END
  END Q[30]

  PIN Q[31]
    DIRECTION OUTPUT ;
    USE SIGNAL ;
    PORT
      LAYER M3 ;
      RECT 10.0 7.0 11.0 8.0 ;
    END
  END Q[31]

END SP512X40M2

LAYER M3
  TYPE ROUTING ;
  DIRECTION HORIZONTAL ;
  PITCH 0.2 ;
  WIDTH 0.1 ;
END M3

LAYER M4
  TYPE ROUTING ;
  DIRECTION VERTICAL ;
  PITCH 0.2 ;
  WIDTH 0.1 ;
END M4

SITE BLOCK
  CLASS BLOCK ;
  SIZE 1.0 BY 1.0 ;
  SYMMETRY X Y ;
END BLOCK


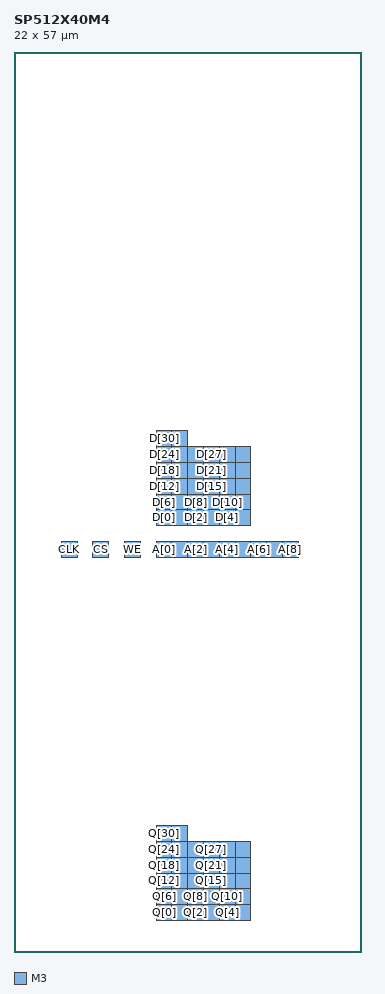
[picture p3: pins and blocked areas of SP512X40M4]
MACRO SP512X40M4
  CLASS BLOCK ;
  ORIGIN 0.0 0.0 ;
  SIZE 22.0 BY 57.0 ;
  SYMMETRY X Y ;
  FOREIGN SP512X40M4 0.0 0.0 ;

  PIN CLK
    DIRECTION INPUT ;
    USE SIGNAL ;
    PORT
      LAYER M3 ;
      RECT 3.0 25.0 4.0 26.0 ;
    END
  END CLK

  PIN CS
    DIRECTION INPUT ;
    USE SIGNAL ;
    PORT
      LAYER M3 ;
      RECT 5.0 25.0 6.0 26.0 ;
    END
  END CS

  PIN WE
    DIRECTION INPUT ;
    USE SIGNAL ;
    PORT
      LAYER M3 ;
      RECT 7.0 25.0 8.0 26.0 ;
    END
  END WE

  PIN A[0]
    DIRECTION INPUT ;
    USE SIGNAL ;
    PORT
      LAYER M3 ;
      RECT 9.0 25.0 10.0 26.0 ;
    END
  END A[0]

  PIN A[1]
    DIRECTION INPUT ;
    USE SIGNAL ;
    PORT
      LAYER M3 ;
      RECT 10.0 25.0 11.0 26.0 ;
    END
  END A[1]

  PIN A[2]
    DIRECTION INPUT ;
    USE SIGNAL ;
    PORT
      LAYER M3 ;
      RECT 11.0 25.0 12.0 26.0 ;
    END
  END A[2]

  PIN A[3]
    DIRECTION INPUT ;
    USE SIGNAL ;
    PORT
      LAYER M3 ;
      RECT 12.0 25.0 13.0 26.0 ;
    END
  END A[3]

  PIN A[4]
    DIRECTION INPUT ;
    USE SIGNAL ;
    PORT
      LAYER M3 ;
      RECT 13.0 25.0 14.0 26.0 ;
    END
  END A[4]

  PIN A[5]
    DIRECTION INPUT ;
    USE SIGNAL ;
    PORT
      LAYER M3 ;
      RECT 14.0 25.0 15.0 26.0 ;
    END
  END A[5]

  PIN A[6]
    DIRECTION INPUT ;
    USE SIGNAL ;
    PORT
      LAYER M3 ;
      RECT 15.0 25.0 16.0 26.0 ;
    END
  END A[6]

  PIN A[7]
    DIRECTION INPUT ;
    USE SIGNAL ;
    PORT
      LAYER M3 ;
      RECT 16.0 25.0 17.0 26.0 ;
    END
  END A[7]

  PIN A[8]
    DIRECTION INPUT ;
    USE SIGNAL ;
    PORT
      LAYER M3 ;
      RECT 17.0 25.0 18.0 26.0 ;
    END
  END A[8]

  PIN D[0]
    DIRECTION INPUT ;
    USE SIGNAL ;
    PORT
      LAYER M3 ;
      RECT 9.0 27.0 10.0 28.0 ;
    END
  END D[0]

  PIN D[1]
    DIRECTION INPUT ;
    USE SIGNAL ;
    PORT
      LAYER M3 ;
      RECT 10.0 27.0 11.0 28.0 ;
    END
  END D[1]

  PIN D[2]
    DIRECTION INPUT ;
    USE SIGNAL ;
    PORT
      LAYER M3 ;
      RECT 11.0 27.0 12.0 28.0 ;
    END
  END D[2]

  PIN D[3]
    DIRECTION INPUT ;
    USE SIGNAL ;
    PORT
      LAYER M3 ;
      RECT 12.0 27.0 13.0 28.0 ;
    END
  END D[3]

  PIN D[4]
    DIRECTION INPUT ;
    USE SIGNAL ;
    PORT
      LAYER M3 ;
      RECT 13.0 27.0 14.0 28.0 ;
    END
  END D[4]

  PIN D[5]
    DIRECTION INPUT ;
    USE SIGNAL ;
    PORT
      LAYER M3 ;
      RECT 14.0 27.0 15.0 28.0 ;
    END
  END D[5]

  PIN D[6]
    DIRECTION INPUT ;
    USE SIGNAL ;
    PORT
      LAYER M3 ;
      RECT 9.0 28.0 10.0 29.0 ;
    END
  END D[6]

  PIN D[7]
    DIRECTION INPUT ;
    USE SIGNAL ;
    PORT
      LAYER M3 ;
      RECT 10.0 28.0 11.0 29.0 ;
    END
  END D[7]

  PIN D[8]
    DIRECTION INPUT ;
    USE SIGNAL ;
    PORT
      LAYER M3 ;
      RECT 11.0 28.0 12.0 29.0 ;
    END
  END D[8]

  PIN D[9]
    DIRECTION INPUT ;
    USE SIGNAL ;
    PORT
      LAYER M3 ;
      RECT 12.0 28.0 13.0 29.0 ;
    END
  END D[9]

  PIN D[10]
    DIRECTION INPUT ;
    USE SIGNAL ;
    PORT
      LAYER M3 ;
      RECT 13.0 28.0 14.0 29.0 ;
    END
  END D[10]

  PIN D[11]
    DIRECTION INPUT ;
    USE SIGNAL ;
    PORT
      LAYER M3 ;
      RECT 14.0 28.0 15.0 29.0 ;
    END
  END D[11]

  PIN D[12]
    DIRECTION INPUT ;
    USE SIGNAL ;
    PORT
      LAYER M3 ;
      RECT 9.0 29.0 10.0 30.0 ;
    END
  END D[12]

  PIN D[13]
    DIRECTION INPUT ;
    USE SIGNAL ;
    PORT
      LAYER M3 ;
      RECT 10.0 29.0 11.0 30.0 ;
    END
  END D[13]

  PIN D[14]
    DIRECTION INPUT ;
    USE SIGNAL ;
    PORT
      LAYER M3 ;
      RECT 11.0 29.0 12.0 30.0 ;
    END
  END D[14]

  PIN D[15]
    DIRECTION INPUT ;
    USE SIGNAL ;
    PORT
      LAYER M3 ;
      RECT 12.0 29.0 13.0 30.0 ;
    END
  END D[15]

  PIN D[16]
    DIRECTION INPUT ;
    USE SIGNAL ;
    PORT
      LAYER M3 ;
      RECT 13.0 29.0 14.0 30.0 ;
    END
  END D[16]

  PIN D[17]
    DIRECTION INPUT ;
    USE SIGNAL ;
    PORT
      LAYER M3 ;
      RECT 14.0 29.0 15.0 30.0 ;
    END
  END D[17]

  PIN D[18]
    DIRECTION INPUT ;
    USE SIGNAL ;
    PORT
      LAYER M3 ;
      RECT 9.0 30.0 10.0 31.0 ;
    END
  END D[18]

  PIN D[19]
    DIRECTION INPUT ;
    USE SIGNAL ;
    PORT
      LAYER M3 ;
      RECT 10.0 30.0 11.0 31.0 ;
    END
  END D[19]

  PIN D[20]
    DIRECTION INPUT ;
    USE SIGNAL ;
    PORT
      LAYER M3 ;
      RECT 11.0 30.0 12.0 31.0 ;
    END
  END D[20]

  PIN D[21]
    DIRECTION INPUT ;
    USE SIGNAL ;
    PORT
      LAYER M3 ;
      RECT 12.0 30.0 13.0 31.0 ;
    END
  END D[21]

  PIN D[22]
    DIRECTION INPUT ;
    USE SIGNAL ;
    PORT
      LAYER M3 ;
      RECT 13.0 30.0 14.0 31.0 ;
    END
  END D[22]

  PIN D[23]
    DIRECTION INPUT ;
    USE SIGNAL ;
    PORT
      LAYER M3 ;
      RECT 14.0 30.0 15.0 31.0 ;
    END
  END D[23]

  PIN D[24]
    DIRECTION INPUT ;
    USE SIGNAL ;
    PORT
      LAYER M3 ;
      RECT 9.0 31.0 10.0 32.0 ;
    END
  END D[24]

  PIN D[25]
    DIRECTION INPUT ;
    USE SIGNAL ;
    PORT
      LAYER M3 ;
      RECT 10.0 31.0 11.0 32.0 ;
    END
  END D[25]

  PIN D[26]
    DIRECTION INPUT ;
    USE SIGNAL ;
    PORT
      LAYER M3 ;
      RECT 11.0 31.0 12.0 32.0 ;
    END
  END D[26]

  PIN D[27]
    DIRECTION INPUT ;
    USE SIGNAL ;
    PORT
      LAYER M3 ;
      RECT 12.0 31.0 13.0 32.0 ;
    END
  END D[27]

  PIN D[28]
    DIRECTION INPUT ;
    USE SIGNAL ;
    PORT
      LAYER M3 ;
      RECT 13.0 31.0 14.0 32.0 ;
    END
  END D[28]

  PIN D[29]
    DIRECTION INPUT ;
    USE SIGNAL ;
    PORT
      LAYER M3 ;
      RECT 14.0 31.0 15.0 32.0 ;
    END
  END D[29]

  PIN D[30]
    DIRECTION INPUT ;
    USE SIGNAL ;
    PORT
      LAYER M3 ;
      RECT 9.0 32.0 10.0 33.0 ;
    END
  END D[30]

  PIN D[31]
    DIRECTION INPUT ;
    USE SIGNAL ;
    PORT
      LAYER M3 ;
      RECT 10.0 32.0 11.0 33.0 ;
    END
  END D[31]

  PIN Q[0]
    DIRECTION OUTPUT ;
    USE SIGNAL ;
    PORT
      LAYER M3 ;
      RECT 9.0 2.0 10.0 3.0 ;
    END
  END Q[0]

  PIN Q[1]
    DIRECTION OUTPUT ;
    USE SIGNAL ;
    PORT
      LAYER M3 ;
      RECT 10.0 2.0 11.0 3.0 ;
    END
  END Q[1]

  PIN Q[2]
    DIRECTION OUTPUT ;
    USE SIGNAL ;
    PORT
      LAYER M3 ;
      RECT 11.0 2.0 12.0 3.0 ;
    END
  END Q[2]

  PIN Q[3]
    DIRECTION OUTPUT ;
    USE SIGNAL ;
    PORT
      LAYER M3 ;
      RECT 12.0 2.0 13.0 3.0 ;
    END
  END Q[3]

  PIN Q[4]
    DIRECTION OUTPUT ;
    USE SIGNAL ;
    PORT
      LAYER M3 ;
      RECT 13.0 2.0 14.0 3.0 ;
    END
  END Q[4]

  PIN Q[5]
    DIRECTION OUTPUT ;
    USE SIGNAL ;
    PORT
      LAYER M3 ;
      RECT 14.0 2.0 15.0 3.0 ;
    END
  END Q[5]

  PIN Q[6]
    DIRECTION OUTPUT ;
    USE SIGNAL ;
    PORT
      LAYER M3 ;
      RECT 9.0 3.0 10.0 4.0 ;
    END
  END Q[6]

  PIN Q[7]
    DIRECTION OUTPUT ;
    USE SIGNAL ;
    PORT
      LAYER M3 ;
      RECT 10.0 3.0 11.0 4.0 ;
    END
  END Q[7]

  PIN Q[8]
    DIRECTION OUTPUT ;
    USE SIGNAL ;
    PORT
      LAYER M3 ;
      RECT 11.0 3.0 12.0 4.0 ;
    END
  END Q[8]

  PIN Q[9]
    DIRECTION OUTPUT ;
    USE SIGNAL ;
    PORT
      LAYER M3 ;
      RECT 12.0 3.0 13.0 4.0 ;
    END
  END Q[9]

  PIN Q[10]
    DIRECTION OUTPUT ;
    USE SIGNAL ;
    PORT
      LAYER M3 ;
      RECT 13.0 3.0 14.0 4.0 ;
    END
  END Q[10]

  PIN Q[11]
    DIRECTION OUTPUT ;
    USE SIGNAL ;
    PORT
      LAYER M3 ;
      RECT 14.0 3.0 15.0 4.0 ;
    END
  END Q[11]

  PIN Q[12]
    DIRECTION OUTPUT ;
    USE SIGNAL ;
    PORT
      LAYER M3 ;
      RECT 9.0 4.0 10.0 5.0 ;
    END
  END Q[12]

  PIN Q[13]
    DIRECTION OUTPUT ;
    USE SIGNAL ;
    PORT
      LAYER M3 ;
      RECT 10.0 4.0 11.0 5.0 ;
    END
  END Q[13]

  PIN Q[14]
    DIRECTION OUTPUT ;
    USE SIGNAL ;
    PORT
      LAYER M3 ;
      RECT 11.0 4.0 12.0 5.0 ;
    END
  END Q[14]

  PIN Q[15]
    DIRECTION OUTPUT ;
    USE SIGNAL ;
    PORT
      LAYER M3 ;
      RECT 12.0 4.0 13.0 5.0 ;
    END
  END Q[15]

  PIN Q[16]
    DIRECTION OUTPUT ;
    USE SIGNAL ;
    PORT
      LAYER M3 ;
      RECT 13.0 4.0 14.0 5.0 ;
    END
  END Q[16]

  PIN Q[17]
    DIRECTION OUTPUT ;
    USE SIGNAL ;
    PORT
      LAYER M3 ;
      RECT 14.0 4.0 15.0 5.0 ;
    END
  END Q[17]

  PIN Q[18]
    DIRECTION OUTPUT ;
    USE SIGNAL ;
    PORT
      LAYER M3 ;
      RECT 9.0 5.0 10.0 6.0 ;
    END
  END Q[18]

  PIN Q[19]
    DIRECTION OUTPUT ;
    USE SIGNAL ;
    PORT
      LAYER M3 ;
      RECT 10.0 5.0 11.0 6.0 ;
    END
  END Q[19]

  PIN Q[20]
    DIRECTION OUTPUT ;
    USE SIGNAL ;
    PORT
      LAYER M3 ;
      RECT 11.0 5.0 12.0 6.0 ;
    END
  END Q[20]

  PIN Q[21]
    DIRECTION OUTPUT ;
    USE SIGNAL ;
    PORT
      LAYER M3 ;
      RECT 12.0 5.0 13.0 6.0 ;
    END
  END Q[21]

  PIN Q[22]
    DIRECTION OUTPUT ;
    USE SIGNAL ;
    PORT
      LAYER M3 ;
      RECT 13.0 5.0 14.0 6.0 ;
    END
  END Q[22]

  PIN Q[23]
    DIRECTION OUTPUT ;
    USE SIGNAL ;
    PORT
      LAYER M3 ;
      RECT 14.0 5.0 15.0 6.0 ;
    END
  END Q[23]

  PIN Q[24]
    DIRECTION OUTPUT ;
    USE SIGNAL ;
    PORT
      LAYER M3 ;
      RECT 9.0 6.0 10.0 7.0 ;
    END
  END Q[24]

  PIN Q[25]
    DIRECTION OUTPUT ;
    USE SIGNAL ;
    PORT
      LAYER M3 ;
      RECT 10.0 6.0 11.0 7.0 ;
    END
  END Q[25]

  PIN Q[26]
    DIRECTION OUTPUT ;
    USE SIGNAL ;
    PORT
      LAYER M3 ;
      RECT 11.0 6.0 12.0 7.0 ;
    END
  END Q[26]

  PIN Q[27]
    DIRECTION OUTPUT ;
    USE SIGNAL ;
    PORT
      LAYER M3 ;
      RECT 12.0 6.0 13.0 7.0 ;
    END
  END Q[27]

  PIN Q[28]
    DIRECTION OUTPUT ;
    USE SIGNAL ;
    PORT
      LAYER M3 ;
      RECT 13.0 6.0 14.0 7.0 ;
    END
  END Q[28]

  PIN Q[29]
    DIRECTION OUTPUT ;
    USE SIGNAL ;
    PORT
      LAYER M3 ;
      RECT 14.0 6.0 15.0 7.0 ;
    END
  END Q[29]

  PIN Q[30]
    DIRECTION OUTPUT ;
    USE SIGNAL ;
    PORT
      LAYER M3 ;
      RECT 9.0 7.0 10.0 8.0 ;
    END
  END Q[30]

  PIN Q[31]
    DIRECTION OUTPUT ;
    USE SIGNAL ;
    PORT
      LAYER M3 ;
      RECT 10.0 7.0 11.0 8.0 ;
    END
  END Q[31]

END SP512X40M4

LAYER M3
  TYPE ROUTING ;
  DIRECTION HORIZONTAL ;
  PITCH 0.2 ;
  WIDTH 0.1 ;
END M3

LAYER M4
  TYPE ROUTING ;
  DIRECTION VERTICAL ;
  PITCH 0.2 ;
  WIDTH 0.1 ;
END M4

SITE BLOCK
  CLASS BLOCK ;
  SIZE 1.0 BY 1.0 ;
  SYMMETRY X Y ;
END BLOCK


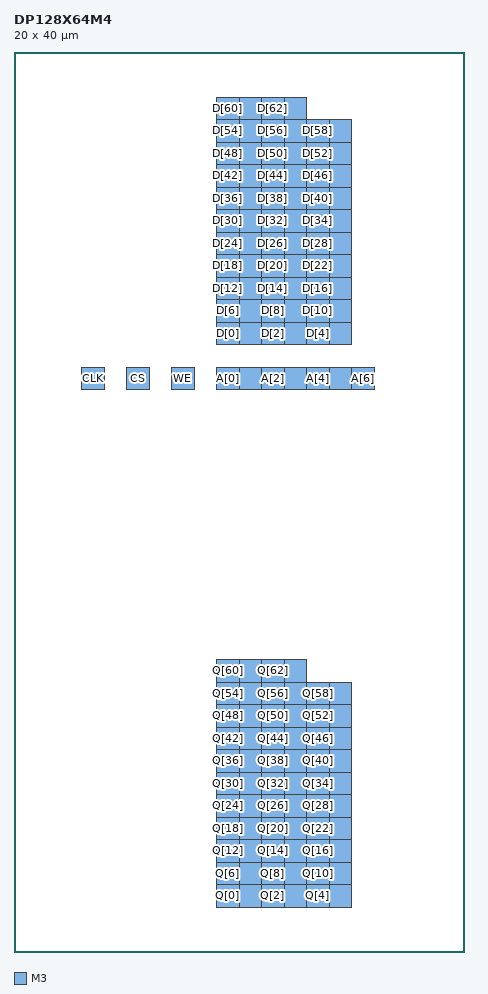
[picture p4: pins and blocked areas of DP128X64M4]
MACRO DP128X64M4
  CLASS BLOCK ;
  ORIGIN 0.0 0.0 ;
  SIZE 20.0 BY 40.0 ;
  SYMMETRY X Y ;
  FOREIGN DP128X64M4 0.0 0.0 ;

  PIN CLK
    DIRECTION INPUT ;
    USE SIGNAL ;
    PORT
      LAYER M3 ;
      RECT 3.0 25.0 4.0 26.0 ;
    END
  END CLK

  PIN CS
    DIRECTION INPUT ;
    USE SIGNAL ;
    PORT
      LAYER M3 ;
      RECT 5.0 25.0 6.0 26.0 ;
    END
  END CS

  PIN WE
    DIRECTION INPUT ;
    USE SIGNAL ;
    PORT
      LAYER M3 ;
      RECT 7.0 25.0 8.0 26.0 ;
    END
  END WE

  PIN A[0]
    DIRECTION INPUT ;
    USE SIGNAL ;
    PORT
      LAYER M3 ;
      RECT 9.0 25.0 10.0 26.0 ;
    END
  END A[0]

  PIN A[1]
    DIRECTION INPUT ;
    USE SIGNAL ;
    PORT
      LAYER M3 ;
      RECT 10.0 25.0 11.0 26.0 ;
    END
  END A[1]

  PIN A[2]
    DIRECTION INPUT ;
    USE SIGNAL ;
    PORT
      LAYER M3 ;
      RECT 11.0 25.0 12.0 26.0 ;
    END
  END A[2]

  PIN A[3]
    DIRECTION INPUT ;
    USE SIGNAL ;
    PORT
      LAYER M3 ;
      RECT 12.0 25.0 13.0 26.0 ;
    END
  END A[3]

  PIN A[4]
    DIRECTION INPUT ;
    USE SIGNAL ;
    PORT
      LAYER M3 ;
      RECT 13.0 25.0 14.0 26.0 ;
    END
  END A[4]

  PIN A[5]
    DIRECTION INPUT ;
    USE SIGNAL ;
    PORT
      LAYER M3 ;
      RECT 14.0 25.0 15.0 26.0 ;
    END
  END A[5]

  PIN A[6]
    DIRECTION INPUT ;
    USE SIGNAL ;
    PORT
      LAYER M3 ;
      RECT 15.0 25.0 16.0 26.0 ;
    END
  END A[6]

  PIN D[0]
    DIRECTION INPUT ;
    USE SIGNAL ;
    PORT
      LAYER M3 ;
      RECT 9.0 27.0 10.0 28.0 ;
    END
  END D[0]

  PIN D[1]
    DIRECTION INPUT ;
    USE SIGNAL ;
    PORT
      LAYER M3 ;
      RECT 10.0 27.0 11.0 28.0 ;
    END
  END D[1]

  PIN D[2]
    DIRECTION INPUT ;
    USE SIGNAL ;
    PORT
      LAYER M3 ;
      RECT 11.0 27.0 12.0 28.0 ;
    END
  END D[2]

  PIN D[3]
    DIRECTION INPUT ;
    USE SIGNAL ;
    PORT
      LAYER M3 ;
      RECT 12.0 27.0 13.0 28.0 ;
    END
  END D[3]

  PIN D[4]
    DIRECTION INPUT ;
    USE SIGNAL ;
    PORT
      LAYER M3 ;
      RECT 13.0 27.0 14.0 28.0 ;
    END
  END D[4]

  PIN D[5]
    DIRECTION INPUT ;
    USE SIGNAL ;
    PORT
      LAYER M3 ;
      RECT 14.0 27.0 15.0 28.0 ;
    END
  END D[5]

  PIN D[6]
    DIRECTION INPUT ;
    USE SIGNAL ;
    PORT
      LAYER M3 ;
      RECT 9.0 28.0 10.0 29.0 ;
    END
  END D[6]

  PIN D[7]
    DIRECTION INPUT ;
    USE SIGNAL ;
    PORT
      LAYER M3 ;
      RECT 10.0 28.0 11.0 29.0 ;
    END
  END D[7]

  PIN D[8]
    DIRECTION INPUT ;
    USE SIGNAL ;
    PORT
      LAYER M3 ;
      RECT 11.0 28.0 12.0 29.0 ;
    END
  END D[8]

  PIN D[9]
    DIRECTION INPUT ;
    USE SIGNAL ;
    PORT
      LAYER M3 ;
      RECT 12.0 28.0 13.0 29.0 ;
    END
  END D[9]

  PIN D[10]
    DIRECTION INPUT ;
    USE SIGNAL ;
    PORT
      LAYER M3 ;
      RECT 13.0 28.0 14.0 29.0 ;
    END
  END D[10]

  PIN D[11]
    DIRECTION INPUT ;
    USE SIGNAL ;
    PORT
      LAYER M3 ;
      RECT 14.0 28.0 15.0 29.0 ;
    END
  END D[11]

  PIN D[12]
    DIRECTION INPUT ;
    USE SIGNAL ;
    PORT
      LAYER M3 ;
      RECT 9.0 29.0 10.0 30.0 ;
    END
  END D[12]

  PIN D[13]
    DIRECTION INPUT ;
    USE SIGNAL ;
    PORT
      LAYER M3 ;
      RECT 10.0 29.0 11.0 30.0 ;
    END
  END D[13]

  PIN D[14]
    DIRECTION INPUT ;
    USE SIGNAL ;
    PORT
      LAYER M3 ;
      RECT 11.0 29.0 12.0 30.0 ;
    END
  END D[14]

  PIN D[15]
    DIRECTION INPUT ;
    USE SIGNAL ;
    PORT
      LAYER M3 ;
      RECT 12.0 29.0 13.0 30.0 ;
    END
  END D[15]

  PIN D[16]
    DIRECTION INPUT ;
    USE SIGNAL ;
    PORT
      LAYER M3 ;
      RECT 13.0 29.0 14.0 30.0 ;
    END
  END D[16]

  PIN D[17]
    DIRECTION INPUT ;
    USE SIGNAL ;
    PORT
      LAYER M3 ;
      RECT 14.0 29.0 15.0 30.0 ;
    END
  END D[17]

  PIN D[18]
    DIRECTION INPUT ;
    USE SIGNAL ;
    PORT
      LAYER M3 ;
      RECT 9.0 30.0 10.0 31.0 ;
    END
  END D[18]

  PIN D[19]
    DIRECTION INPUT ;
    USE SIGNAL ;
    PORT
      LAYER M3 ;
      RECT 10.0 30.0 11.0 31.0 ;
    END
  END D[19]

  PIN D[20]
    DIRECTION INPUT ;
    USE SIGNAL ;
    PORT
      LAYER M3 ;
      RECT 11.0 30.0 12.0 31.0 ;
    END
  END D[20]

  PIN D[21]
    DIRECTION INPUT ;
    USE SIGNAL ;
    PORT
      LAYER M3 ;
      RECT 12.0 30.0 13.0 31.0 ;
    END
  END D[21]

  PIN D[22]
    DIRECTION INPUT ;
    USE SIGNAL ;
    PORT
      LAYER M3 ;
      RECT 13.0 30.0 14.0 31.0 ;
    END
  END D[22]

  PIN D[23]
    DIRECTION INPUT ;
    USE SIGNAL ;
    PORT
      LAYER M3 ;
      RECT 14.0 30.0 15.0 31.0 ;
    END
  END D[23]

  PIN D[24]
    DIRECTION INPUT ;
    USE SIGNAL ;
    PORT
      LAYER M3 ;
      RECT 9.0 31.0 10.0 32.0 ;
    END
  END D[24]

  PIN D[25]
    DIRECTION INPUT ;
    USE SIGNAL ;
    PORT
      LAYER M3 ;
      RECT 10.0 31.0 11.0 32.0 ;
    END
  END D[25]

  PIN D[26]
    DIRECTION INPUT ;
    USE SIGNAL ;
    PORT
      LAYER M3 ;
      RECT 11.0 31.0 12.0 32.0 ;
    END
  END D[26]

  PIN D[27]
    DIRECTION INPUT ;
    USE SIGNAL ;
    PORT
      LAYER M3 ;
      RECT 12.0 31.0 13.0 32.0 ;
    END
  END D[27]

  PIN D[28]
    DIRECTION INPUT ;
    USE SIGNAL ;
    PORT
      LAYER M3 ;
      RECT 13.0 31.0 14.0 32.0 ;
    END
  END D[28]

  PIN D[29]
    DIRECTION INPUT ;
    USE SIGNAL ;
    PORT
      LAYER M3 ;
      RECT 14.0 31.0 15.0 32.0 ;
    END
  END D[29]

  PIN D[30]
    DIRECTION INPUT ;
    USE SIGNAL ;
    PORT
      LAYER M3 ;
      RECT 9.0 32.0 10.0 33.0 ;
    END
  END D[30]

  PIN D[31]
    DIRECTION INPUT ;
    USE SIGNAL ;
    PORT
      LAYER M3 ;
      RECT 10.0 32.0 11.0 33.0 ;
    END
  END D[31]

  PIN D[32]
    DIRECTION INPUT ;
    USE SIGNAL ;
    PORT
      LAYER M3 ;
      RECT 11.0 32.0 12.0 33.0 ;
    END
  END D[32]

  PIN D[33]
    DIRECTION INPUT ;
    USE SIGNAL ;
    PORT
      LAYER M3 ;
      RECT 12.0 32.0 13.0 33.0 ;
    END
  END D[33]

  PIN D[34]
    DIRECTION INPUT ;
    USE SIGNAL ;
    PORT
      LAYER M3 ;
      RECT 13.0 32.0 14.0 33.0 ;
    END
  END D[34]

  PIN D[35]
    DIRECTION INPUT ;
    USE SIGNAL ;
    PORT
      LAYER M3 ;
      RECT 14.0 32.0 15.0 33.0 ;
    END
  END D[35]

  PIN D[36]
    DIRECTION INPUT ;
    USE SIGNAL ;
    PORT
      LAYER M3 ;
      RECT 9.0 33.0 10.0 34.0 ;
    END
  END D[36]

  PIN D[37]
    DIRECTION INPUT ;
    USE SIGNAL ;
    PORT
      LAYER M3 ;
      RECT 10.0 33.0 11.0 34.0 ;
    END
  END D[37]

  PIN D[38]
    DIRECTION INPUT ;
    USE SIGNAL ;
    PORT
      LAYER M3 ;
      RECT 11.0 33.0 12.0 34.0 ;
    END
  END D[38]

  PIN D[39]
    DIRECTION INPUT ;
    USE SIGNAL ;
    PORT
      LAYER M3 ;
      RECT 12.0 33.0 13.0 34.0 ;
    END
  END D[39]

  PIN D[40]
    DIRECTION INPUT ;
    USE SIGNAL ;
    PORT
      LAYER M3 ;
      RECT 13.0 33.0 14.0 34.0 ;
    END
  END D[40]

  PIN D[41]
    DIRECTION INPUT ;
    USE SIGNAL ;
    PORT
      LAYER M3 ;
      RECT 14.0 33.0 15.0 34.0 ;
    END
  END D[41]

  PIN D[42]
    DIRECTION INPUT ;
    USE SIGNAL ;
    PORT
      LAYER M3 ;
      RECT 9.0 34.0 10.0 35.0 ;
    END
  END D[42]

  PIN D[43]
    DIRECTION INPUT ;
    USE SIGNAL ;
    PORT
      LAYER M3 ;
      RECT 10.0 34.0 11.0 35.0 ;
    END
  END D[43]

  PIN D[44]
    DIRECTION INPUT ;
    USE SIGNAL ;
    PORT
      LAYER M3 ;
      RECT 11.0 34.0 12.0 35.0 ;
    END
  END D[44]

  PIN D[45]
    DIRECTION INPUT ;
    USE SIGNAL ;
    PORT
      LAYER M3 ;
      RECT 12.0 34.0 13.0 35.0 ;
    END
  END D[45]

  PIN D[46]
    DIRECTION INPUT ;
    USE SIGNAL ;
    PORT
      LAYER M3 ;
      RECT 13.0 34.0 14.0 35.0 ;
    END
  END D[46]

  PIN D[47]
    DIRECTION INPUT ;
    USE SIGNAL ;
    PORT
      LAYER M3 ;
      RECT 14.0 34.0 15.0 35.0 ;
    END
  END D[47]

  PIN D[48]
    DIRECTION INPUT ;
    USE SIGNAL ;
    PORT
      LAYER M3 ;
      RECT 9.0 35.0 10.0 36.0 ;
    END
  END D[48]

  PIN D[49]
    DIRECTION INPUT ;
    USE SIGNAL ;
    PORT
      LAYER M3 ;
      RECT 10.0 35.0 11.0 36.0 ;
    END
  END D[49]

  PIN D[50]
    DIRECTION INPUT ;
    USE SIGNAL ;
    PORT
      LAYER M3 ;
      RECT 11.0 35.0 12.0 36.0 ;
    END
  END D[50]

  PIN D[51]
    DIRECTION INPUT ;
    USE SIGNAL ;
    PORT
      LAYER M3 ;
      RECT 12.0 35.0 13.0 36.0 ;
    END
  END D[51]

  PIN D[52]
    DIRECTION INPUT ;
    USE SIGNAL ;
    PORT
      LAYER M3 ;
      RECT 13.0 35.0 14.0 36.0 ;
    END
  END D[52]

  PIN D[53]
    DIRECTION INPUT ;
    USE SIGNAL ;
    PORT
      LAYER M3 ;
      RECT 14.0 35.0 15.0 36.0 ;
    END
  END D[53]

  PIN D[54]
    DIRECTION INPUT ;
    USE SIGNAL ;
    PORT
      LAYER M3 ;
      RECT 9.0 36.0 10.0 37.0 ;
    END
  END D[54]

  PIN D[55]
    DIRECTION INPUT ;
    USE SIGNAL ;
    PORT
      LAYER M3 ;
      RECT 10.0 36.0 11.0 37.0 ;
    END
  END D[55]

  PIN D[56]
    DIRECTION INPUT ;
    USE SIGNAL ;
    PORT
      LAYER M3 ;
      RECT 11.0 36.0 12.0 37.0 ;
    END
  END D[56]

  PIN D[57]
    DIRECTION INPUT ;
    USE SIGNAL ;
    PORT
      LAYER M3 ;
      RECT 12.0 36.0 13.0 37.0 ;
    END
  END D[57]

  PIN D[58]
    DIRECTION INPUT ;
    USE SIGNAL ;
    PORT
      LAYER M3 ;
      RECT 13.0 36.0 14.0 37.0 ;
    END
  END D[58]

  PIN D[59]
    DIRECTION INPUT ;
    USE SIGNAL ;
    PORT
      LAYER M3 ;
      RECT 14.0 36.0 15.0 37.0 ;
    END
  END D[59]

  PIN D[60]
    DIRECTION INPUT ;
    USE SIGNAL ;
    PORT
      LAYER M3 ;
      RECT 9.0 37.0 10.0 38.0 ;
    END
  END D[60]

  PIN D[61]
    DIRECTION INPUT ;
    USE SIGNAL ;
    PORT
      LAYER M3 ;
      RECT 10.0 37.0 11.0 38.0 ;
    END
  END D[61]

  PIN D[62]
    DIRECTION INPUT ;
    USE SIGNAL ;
    PORT
      LAYER M3 ;
      RECT 11.0 37.0 12.0 38.0 ;
    END
  END D[62]

  PIN D[63]
    DIRECTION INPUT ;
    USE SIGNAL ;
    PORT
      LAYER M3 ;
      RECT 12.0 37.0 13.0 38.0 ;
    END
  END D[63]

  PIN Q[0]
    DIRECTION OUTPUT ;
    USE SIGNAL ;
    PORT
      LAYER M3 ;
      RECT 9.0 2.0 10.0 3.0 ;
    END
  END Q[0]

  PIN Q[1]
    DIRECTION OUTPUT ;
    USE SIGNAL ;
    PORT
      LAYER M3 ;
      RECT 10.0 2.0 11.0 3.0 ;
    END
  END Q[1]

  PIN Q[2]
    DIRECTION OUTPUT ;
    USE SIGNAL ;
    PORT
      LAYER M3 ;
      RECT 11.0 2.0 12.0 3.0 ;
    END
  END Q[2]

  PIN Q[3]
    DIRECTION OUTPUT ;
    USE SIGNAL ;
    PORT
      LAYER M3 ;
      RECT 12.0 2.0 13.0 3.0 ;
    END
  END Q[3]

  PIN Q[4]
    DIRECTION OUTPUT ;
    USE SIGNAL ;
    PORT
      LAYER M3 ;
      RECT 13.0 2.0 14.0 3.0 ;
    END
  END Q[4]

  PIN Q[5]
    DIRECTION OUTPUT ;
    USE SIGNAL ;
    PORT
      LAYER M3 ;
      RECT 14.0 2.0 15.0 3.0 ;
    END
  END Q[5]

  PIN Q[6]
    DIRECTION OUTPUT ;
    USE SIGNAL ;
    PORT
      LAYER M3 ;
      RECT 9.0 3.0 10.0 4.0 ;
    END
  END Q[6]

  PIN Q[7]
    DIRECTION OUTPUT ;
    USE SIGNAL ;
    PORT
      LAYER M3 ;
      RECT 10.0 3.0 11.0 4.0 ;
    END
  END Q[7]

  PIN Q[8]
    DIRECTION OUTPUT ;
    USE SIGNAL ;
    PORT
      LAYER M3 ;
      RECT 11.0 3.0 12.0 4.0 ;
    END
  END Q[8]

  PIN Q[9]
    DIRECTION OUTPUT ;
    USE SIGNAL ;
    PORT
      LAYER M3 ;
      RECT 12.0 3.0 13.0 4.0 ;
    END
  END Q[9]

  PIN Q[10]
    DIRECTION OUTPUT ;
    USE SIGNAL ;
    PORT
      LAYER M3 ;
      RECT 13.0 3.0 14.0 4.0 ;
    END
  END Q[10]

  PIN Q[11]
    DIRECTION OUTPUT ;
    USE SIGNAL ;
    PORT
      LAYER M3 ;
      RECT 14.0 3.0 15.0 4.0 ;
    END
  END Q[11]

  PIN Q[12]
    DIRECTION OUTPUT ;
    USE SIGNAL ;
    PORT
      LAYER M3 ;
      RECT 9.0 4.0 10.0 5.0 ;
    END
  END Q[12]

  PIN Q[13]
    DIRECTION OUTPUT ;
    USE SIGNAL ;
    PORT
      LAYER M3 ;
      RECT 10.0 4.0 11.0 5.0 ;
    END
  END Q[13]

  PIN Q[14]
    DIRECTION OUTPUT ;
    USE SIGNAL ;
    PORT
      LAYER M3 ;
      RECT 11.0 4.0 12.0 5.0 ;
    END
  END Q[14]

  PIN Q[15]
    DIRECTION OUTPUT ;
    USE SIGNAL ;
    PORT
      LAYER M3 ;
      RECT 12.0 4.0 13.0 5.0 ;
    END
  END Q[15]

  PIN Q[16]
    DIRECTION OUTPUT ;
    USE SIGNAL ;
    PORT
      LAYER M3 ;
      RECT 13.0 4.0 14.0 5.0 ;
    END
  END Q[16]

  PIN Q[17]
    DIRECTION OUTPUT ;
    USE SIGNAL ;
    PORT
      LAYER M3 ;
      RECT 14.0 4.0 15.0 5.0 ;
    END
  END Q[17]

  PIN Q[18]
    DIRECTION OUTPUT ;
    USE SIGNAL ;
    PORT
      LAYER M3 ;
      RECT 9.0 5.0 10.0 6.0 ;
    END
  END Q[18]

  PIN Q[19]
    DIRECTION OUTPUT ;
    USE SIGNAL ;
    PORT
      LAYER M3 ;
      RECT 10.0 5.0 11.0 6.0 ;
    END
  END Q[19]

  PIN Q[20]
    DIRECTION OUTPUT ;
    USE SIGNAL ;
    PORT
      LAYER M3 ;
      RECT 11.0 5.0 12.0 6.0 ;
    END
  END Q[20]

  PIN Q[21]
    DIRECTION OUTPUT ;
    USE SIGNAL ;
    PORT
      LAYER M3 ;
      RECT 12.0 5.0 13.0 6.0 ;
    END
  END Q[21]

  PIN Q[22]
    DIRECTION OUTPUT ;
    USE SIGNAL ;
    PORT
      LAYER M3 ;
      RECT 13.0 5.0 14.0 6.0 ;
    END
  END Q[22]

  PIN Q[23]
    DIRECTION OUTPUT ;
    USE SIGNAL ;
    PORT
      LAYER M3 ;
      RECT 14.0 5.0 15.0 6.0 ;
    END
  END Q[23]

  PIN Q[24]
    DIRECTION OUTPUT ;
    USE SIGNAL ;
    PORT
      LAYER M3 ;
      RECT 9.0 6.0 10.0 7.0 ;
    END
  END Q[24]

  PIN Q[25]
    DIRECTION OUTPUT ;
    USE SIGNAL ;
    PORT
      LAYER M3 ;
      RECT 10.0 6.0 11.0 7.0 ;
    END
  END Q[25]

  PIN Q[26]
    DIRECTION OUTPUT ;
    USE SIGNAL ;
    PORT
      LAYER M3 ;
      RECT 11.0 6.0 12.0 7.0 ;
    END
  END Q[26]

  PIN Q[27]
    DIRECTION OUTPUT ;
    USE SIGNAL ;
    PORT
      LAYER M3 ;
      RECT 12.0 6.0 13.0 7.0 ;
    END
  END Q[27]

  PIN Q[28]
    DIRECTION OUTPUT ;
    USE SIGNAL ;
    PORT
      LAYER M3 ;
      RECT 13.0 6.0 14.0 7.0 ;
    END
  END Q[28]

  PIN Q[29]
    DIRECTION OUTPUT ;
    USE SIGNAL ;
    PORT
      LAYER M3 ;
      RECT 14.0 6.0 15.0 7.0 ;
    END
  END Q[29]

  PIN Q[30]
    DIRECTION OUTPUT ;
    USE SIGNAL ;
    PORT
      LAYER M3 ;
      RECT 9.0 7.0 10.0 8.0 ;
    END
  END Q[30]

  PIN Q[31]
    DIRECTION OUTPUT ;
    USE SIGNAL ;
    PORT
      LAYER M3 ;
      RECT 10.0 7.0 11.0 8.0 ;
    END
  END Q[31]

  PIN Q[32]
    DIRECTION OUTPUT ;
    USE SIGNAL ;
    PORT
      LAYER M3 ;
      RECT 11.0 7.0 12.0 8.0 ;
    END
  END Q[32]

  PIN Q[33]
    DIRECTION OUTPUT ;
    USE SIGNAL ;
    PORT
      LAYER M3 ;
      RECT 12.0 7.0 13.0 8.0 ;
    END
  END Q[33]

  PIN Q[34]
    DIRECTION OUTPUT ;
    USE SIGNAL ;
    PORT
      LAYER M3 ;
      RECT 13.0 7.0 14.0 8.0 ;
    END
  END Q[34]

  PIN Q[35]
    DIRECTION OUTPUT ;
    USE SIGNAL ;
    PORT
      LAYER M3 ;
      RECT 14.0 7.0 15.0 8.0 ;
    END
  END Q[35]

  PIN Q[36]
    DIRECTION OUTPUT ;
    USE SIGNAL ;
    PORT
      LAYER M3 ;
      RECT 9.0 8.0 10.0 9.0 ;
    END
  END Q[36]

  PIN Q[37]
    DIRECTION OUTPUT ;
    USE SIGNAL ;
    PORT
      LAYER M3 ;
      RECT 10.0 8.0 11.0 9.0 ;
    END
  END Q[37]

  PIN Q[38]
    DIRECTION OUTPUT ;
    USE SIGNAL ;
    PORT
      LAYER M3 ;
      RECT 11.0 8.0 12.0 9.0 ;
    END
  END Q[38]

  PIN Q[39]
    DIRECTION OUTPUT ;
    USE SIGNAL ;
    PORT
      LAYER M3 ;
      RECT 12.0 8.0 13.0 9.0 ;
    END
  END Q[39]

  PIN Q[40]
    DIRECTION OUTPUT ;
    USE SIGNAL ;
    PORT
      LAYER M3 ;
      RECT 13.0 8.0 14.0 9.0 ;
    END
  END Q[40]

  PIN Q[41]
    DIRECTION OUTPUT ;
    USE SIGNAL ;
    PORT
      LAYER M3 ;
      RECT 14.0 8.0 15.0 9.0 ;
    END
  END Q[41]

  PIN Q[42]
    DIRECTION OUTPUT ;
    USE SIGNAL ;
    PORT
      LAYER M3 ;
      RECT 9.0 9.0 10.0 10.0 ;
    END
  END Q[42]

  PIN Q[43]
    DIRECTION OUTPUT ;
    USE SIGNAL ;
    PORT
      LAYER M3 ;
      RECT 10.0 9.0 11.0 10.0 ;
    END
  END Q[43]

  PIN Q[44]
    DIRECTION OUTPUT ;
    USE SIGNAL ;
    PORT
      LAYER M3 ;
      RECT 11.0 9.0 12.0 10.0 ;
    END
  END Q[44]

  PIN Q[45]
    DIRECTION OUTPUT ;
    USE SIGNAL ;
    PORT
      LAYER M3 ;
      RECT 12.0 9.0 13.0 10.0 ;
    END
  END Q[45]

  PIN Q[46]
    DIRECTION OUTPUT ;
    USE SIGNAL ;
    PORT
      LAYER M3 ;
      RECT 13.0 9.0 14.0 10.0 ;
    END
  END Q[46]

  PIN Q[47]
    DIRECTION OUTPUT ;
    USE SIGNAL ;
    PORT
      LAYER M3 ;
      RECT 14.0 9.0 15.0 10.0 ;
    END
  END Q[47]

  PIN Q[48]
    DIRECTION OUTPUT ;
    USE SIGNAL ;
    PORT
      LAYER M3 ;
      RECT 9.0 10.0 10.0 11.0 ;
    END
  END Q[48]

  PIN Q[49]
    DIRECTION OUTPUT ;
    USE SIGNAL ;
    PORT
      LAYER M3 ;
      RECT 10.0 10.0 11.0 11.0 ;
    END
  END Q[49]

  PIN Q[50]
    DIRECTION OUTPUT ;
    USE SIGNAL ;
    PORT
      LAYER M3 ;
      RECT 11.0 10.0 12.0 11.0 ;
    END
  END Q[50]

  PIN Q[51]
    DIRECTION OUTPUT ;
    USE SIGNAL ;
    PORT
      LAYER M3 ;
      RECT 12.0 10.0 13.0 11.0 ;
    END
  END Q[51]

  PIN Q[52]
    DIRECTION OUTPUT ;
    USE SIGNAL ;
    PORT
      LAYER M3 ;
      RECT 13.0 10.0 14.0 11.0 ;
    END
  END Q[52]

  PIN Q[53]
    DIRECTION OUTPUT ;
    USE SIGNAL ;
    PORT
      LAYER M3 ;
      RECT 14.0 10.0 15.0 11.0 ;
    END
  END Q[53]

  PIN Q[54]
    DIRECTION OUTPUT ;
    USE SIGNAL ;
    PORT
      LAYER M3 ;
      RECT 9.0 11.0 10.0 12.0 ;
    END
  END Q[54]

  PIN Q[55]
    DIRECTION OUTPUT ;
    USE SIGNAL ;
    PORT
      LAYER M3 ;
      RECT 10.0 11.0 11.0 12.0 ;
    END
  END Q[55]

  PIN Q[56]
    DIRECTION OUTPUT ;
    USE SIGNAL ;
    PORT
      LAYER M3 ;
      RECT 11.0 11.0 12.0 12.0 ;
    END
  END Q[56]

  PIN Q[57]
    DIRECTION OUTPUT ;
    USE SIGNAL ;
    PORT
      LAYER M3 ;
      RECT 12.0 11.0 13.0 12.0 ;
    END
  END Q[57]

  PIN Q[58]
    DIRECTION OUTPUT ;
    USE SIGNAL ;
    PORT
      LAYER M3 ;
      RECT 13.0 11.0 14.0 12.0 ;
    END
  END Q[58]

  PIN Q[59]
    DIRECTION OUTPUT ;
    USE SIGNAL ;
    PORT
      LAYER M3 ;
      RECT 14.0 11.0 15.0 12.0 ;
    END
  END Q[59]

  PIN Q[60]
    DIRECTION OUTPUT ;
    USE SIGNAL ;
    PORT
      LAYER M3 ;
      RECT 9.0 12.0 10.0 13.0 ;
    END
  END Q[60]

  PIN Q[61]
    DIRECTION OUTPUT ;
    USE SIGNAL ;
    PORT
      LAYER M3 ;
      RECT 10.0 12.0 11.0 13.0 ;
    END
  END Q[61]

  PIN Q[62]
    DIRECTION OUTPUT ;
    USE SIGNAL ;
    PORT
      LAYER M3 ;
      RECT 11.0 12.0 12.0 13.0 ;
    END
  END Q[62]

  PIN Q[63]
    DIRECTION OUTPUT ;
    USE SIGNAL ;
    PORT
      LAYER M3 ;
      RECT 12.0 12.0 13.0 13.0 ;
    END
  END Q[63]

END DP128X64M4

LAYER M3
  TYPE ROUTING ;
  DIRECTION HORIZONTAL ;
  PITCH 0.2 ;
  WIDTH 0.1 ;
END M3

LAYER M4
  TYPE ROUTING ;
  DIRECTION VERTICAL ;
  PITCH 0.2 ;
  WIDTH 0.1 ;
END M4

SITE BLOCK
  CLASS BLOCK ;
  SIZE 1.0 BY 1.0 ;
  SYMMETRY X Y ;
END BLOCK


END LIBRARY
